VERSION 5.7 ;
  NOWIREEXTENSIONATPIN ON ;
  DIVIDERCHAR "/" ;
  BUSBITCHARS "[]" ;
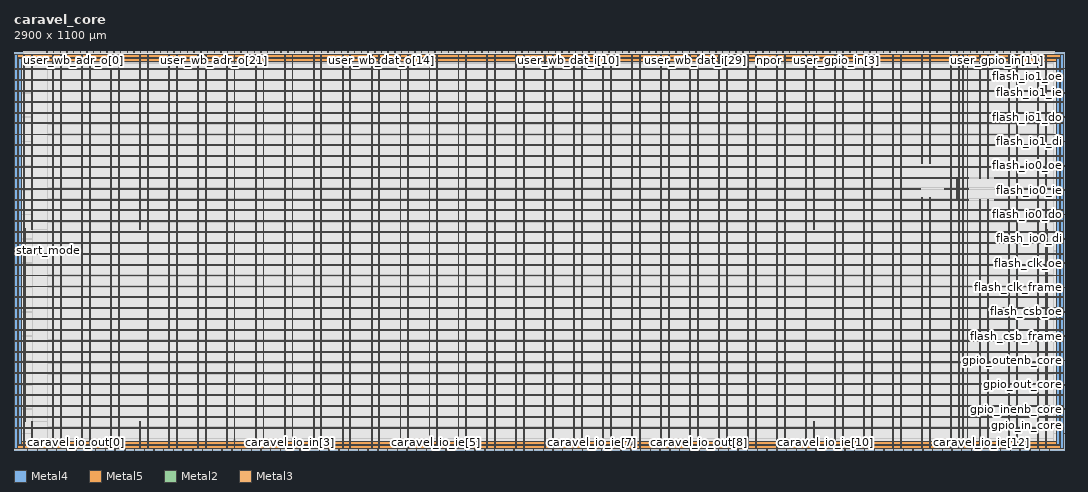
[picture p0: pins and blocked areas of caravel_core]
MACRO caravel_core
  CLASS BLOCK ;
  FOREIGN caravel_core ;
  ORIGIN 0.000 0.000 ;
  SIZE 2900.000 BY 1100.000 ;
  PIN VDD
    DIRECTION INOUT ;
    USE POWER ;
    PORT
      LAYER Metal4 ;
        RECT 11.080 15.360 20.080 1082.240 ;
    END
    PORT
      LAYER Metal5 ;
        RECT 11.080 15.360 2887.480 24.360 ;
    END
    PORT
      LAYER Metal5 ;
        RECT 11.080 1073.240 2887.480 1082.240 ;
    END
    PORT
      LAYER Metal4 ;
        RECT 2878.480 15.360 2887.480 1082.240 ;
    END
    PORT
      LAYER Metal4 ;
        RECT 26.330 4.360 28.830 1093.240 ;
    END
    PORT
      LAYER Metal4 ;
        RECT 106.330 4.360 108.830 1093.240 ;
    END
    PORT
      LAYER Metal4 ;
        RECT 186.330 4.360 188.830 1093.240 ;
    END
    PORT
      LAYER Metal4 ;
        RECT 266.330 4.360 268.830 1093.240 ;
    END
    PORT
      LAYER Metal4 ;
        RECT 346.330 4.360 348.830 78.730 ;
    END
    PORT
      LAYER Metal4 ;
        RECT 346.330 609.370 348.830 1093.240 ;
    END
    PORT
      LAYER Metal4 ;
        RECT 426.330 4.360 428.830 1093.240 ;
    END
    PORT
      LAYER Metal4 ;
        RECT 506.330 4.360 508.830 1093.240 ;
    END
    PORT
      LAYER Metal4 ;
        RECT 586.330 4.360 588.830 1093.240 ;
    END
    PORT
      LAYER Metal4 ;
        RECT 666.330 4.360 668.830 1093.240 ;
    END
    PORT
      LAYER Metal4 ;
        RECT 746.330 4.360 748.830 1093.240 ;
    END
    PORT
      LAYER Metal4 ;
        RECT 826.330 4.360 828.830 1093.240 ;
    END
    PORT
      LAYER Metal4 ;
        RECT 906.330 4.360 908.830 1093.240 ;
    END
    PORT
      LAYER Metal4 ;
        RECT 986.330 4.360 988.830 1093.240 ;
    END
    PORT
      LAYER Metal4 ;
        RECT 1066.330 4.360 1068.830 1093.240 ;
    END
    PORT
      LAYER Metal4 ;
        RECT 1146.330 4.360 1148.830 1093.240 ;
    END
    PORT
      LAYER Metal4 ;
        RECT 1226.330 4.360 1228.830 1093.240 ;
    END
    PORT
      LAYER Metal4 ;
        RECT 1306.330 4.360 1308.830 1093.240 ;
    END
    PORT
      LAYER Metal4 ;
        RECT 1386.330 4.360 1388.830 1093.240 ;
    END
    PORT
      LAYER Metal4 ;
        RECT 1466.330 4.360 1468.830 1093.240 ;
    END
    PORT
      LAYER Metal4 ;
        RECT 1546.330 4.360 1548.830 1093.240 ;
    END
    PORT
      LAYER Metal4 ;
        RECT 1626.330 4.360 1628.830 1093.240 ;
    END
    PORT
      LAYER Metal4 ;
        RECT 1706.330 4.360 1708.830 1093.240 ;
    END
    PORT
      LAYER Metal4 ;
        RECT 1786.330 4.360 1788.830 1093.240 ;
    END
    PORT
      LAYER Metal4 ;
        RECT 1866.330 4.360 1868.830 1093.240 ;
    END
    PORT
      LAYER Metal4 ;
        RECT 1946.330 4.360 1948.830 1093.240 ;
    END
    PORT
      LAYER Metal4 ;
        RECT 2026.330 4.360 2028.830 1093.240 ;
    END
    PORT
      LAYER Metal4 ;
        RECT 2106.330 4.360 2108.830 1093.240 ;
    END
    PORT
      LAYER Metal4 ;
        RECT 2186.330 4.360 2188.830 1093.240 ;
    END
    PORT
      LAYER Metal4 ;
        RECT 2266.330 4.360 2268.830 1093.240 ;
    END
    PORT
      LAYER Metal4 ;
        RECT 2346.330 4.360 2348.830 1093.240 ;
    END
    PORT
      LAYER Metal4 ;
        RECT 2426.330 4.360 2428.830 1093.240 ;
    END
    PORT
      LAYER Metal4 ;
        RECT 2506.330 4.360 2508.830 697.970 ;
    END
    PORT
      LAYER Metal4 ;
        RECT 2506.330 791.630 2508.830 1093.240 ;
    END
    PORT
      LAYER Metal4 ;
        RECT 2586.330 4.360 2588.830 1093.240 ;
    END
    PORT
      LAYER Metal4 ;
        RECT 2666.330 4.360 2668.830 691.730 ;
    END
    PORT
      LAYER Metal4 ;
        RECT 2666.330 749.725 2668.830 1093.240 ;
    END
    PORT
      LAYER Metal4 ;
        RECT 2746.330 4.360 2748.830 1093.240 ;
    END
    PORT
      LAYER Metal4 ;
        RECT 2826.330 4.360 2828.830 1093.240 ;
    END
    PORT
      LAYER Metal5 ;
        RECT 0.080 60.760 2898.480 63.260 ;
    END
    PORT
      LAYER Metal5 ;
        RECT 0.080 120.760 2898.480 123.260 ;
    END
    PORT
      LAYER Metal5 ;
        RECT 0.080 180.760 2898.480 183.260 ;
    END
    PORT
      LAYER Metal5 ;
        RECT 0.080 240.760 2898.480 243.260 ;
    END
    PORT
      LAYER Metal5 ;
        RECT 0.080 300.760 2898.480 303.260 ;
    END
    PORT
      LAYER Metal5 ;
        RECT 0.080 360.760 2898.480 363.260 ;
    END
    PORT
      LAYER Metal5 ;
        RECT 0.080 420.760 2898.480 423.260 ;
    END
    PORT
      LAYER Metal5 ;
        RECT 0.080 480.760 2898.480 483.260 ;
    END
    PORT
      LAYER Metal5 ;
        RECT 0.080 540.760 2898.480 543.260 ;
    END
    PORT
      LAYER Metal5 ;
        RECT 0.080 600.760 2898.480 603.260 ;
    END
    PORT
      LAYER Metal5 ;
        RECT 0.080 660.760 2898.480 663.260 ;
    END
    PORT
      LAYER Metal5 ;
        RECT 0.080 720.760 2504.180 723.260 ;
    END
    PORT
      LAYER Metal5 ;
        RECT 0.080 780.760 2898.480 783.260 ;
    END
    PORT
      LAYER Metal5 ;
        RECT 0.080 840.760 2898.480 843.260 ;
    END
    PORT
      LAYER Metal5 ;
        RECT 0.080 900.760 2898.480 903.260 ;
    END
    PORT
      LAYER Metal5 ;
        RECT 0.080 960.760 2898.480 963.260 ;
    END
    PORT
      LAYER Metal5 ;
        RECT 0.080 1020.760 2898.480 1023.260 ;
    END
    PORT
      LAYER Metal5 ;
        RECT 2570.860 720.760 2635.895 723.260 ;
    END
    PORT
      LAYER Metal5 ;
        RECT 2707.455 720.760 2898.480 723.260 ;
    END
    PORT
      LAYER Metal4 ;
        RECT 2620.830 4.360 2623.330 1093.240 ;
    END
    PORT
      LAYER Metal4 ;
        RECT 2603.095 689.620 2604.345 752.940 ;
    END
    PORT
      LAYER Metal4 ;
        RECT 2851.670 74.180 2854.170 607.900 ;
    END
  END VDD
  PIN VSS
    DIRECTION INOUT ;
    USE GROUND ;
    PORT
      LAYER Metal4 ;
        RECT 0.080 4.360 9.080 1093.240 ;
    END
    PORT
      LAYER Metal5 ;
        RECT 0.080 4.360 2898.480 13.360 ;
    END
    PORT
      LAYER Metal5 ;
        RECT 0.080 1084.240 2898.480 1093.240 ;
    END
    PORT
      LAYER Metal4 ;
        RECT 2889.480 4.360 2898.480 1093.240 ;
    END
    PORT
      LAYER Metal4 ;
        RECT 47.830 4.360 50.330 78.730 ;
    END
    PORT
      LAYER Metal4 ;
        RECT 47.830 609.370 50.330 1093.240 ;
    END
    PORT
      LAYER Metal4 ;
        RECT 127.830 4.360 130.330 1093.240 ;
    END
    PORT
      LAYER Metal4 ;
        RECT 207.830 4.360 210.330 1093.240 ;
    END
    PORT
      LAYER Metal4 ;
        RECT 287.830 4.360 290.330 1093.240 ;
    END
    PORT
      LAYER Metal4 ;
        RECT 367.830 4.360 370.330 1093.240 ;
    END
    PORT
      LAYER Metal4 ;
        RECT 447.830 4.360 450.330 1093.240 ;
    END
    PORT
      LAYER Metal4 ;
        RECT 527.830 4.360 530.330 1093.240 ;
    END
    PORT
      LAYER Metal4 ;
        RECT 607.830 4.360 610.330 1093.240 ;
    END
    PORT
      LAYER Metal4 ;
        RECT 687.830 4.360 690.330 1093.240 ;
    END
    PORT
      LAYER Metal4 ;
        RECT 767.830 4.360 770.330 1093.240 ;
    END
    PORT
      LAYER Metal4 ;
        RECT 847.830 4.360 850.330 1093.240 ;
    END
    PORT
      LAYER Metal4 ;
        RECT 927.830 4.360 930.330 1093.240 ;
    END
    PORT
      LAYER Metal4 ;
        RECT 1007.830 4.360 1010.330 1093.240 ;
    END
    PORT
      LAYER Metal4 ;
        RECT 1087.830 4.360 1090.330 1093.240 ;
    END
    PORT
      LAYER Metal4 ;
        RECT 1167.830 4.360 1170.330 1093.240 ;
    END
    PORT
      LAYER Metal4 ;
        RECT 1247.830 4.360 1250.330 1093.240 ;
    END
    PORT
      LAYER Metal4 ;
        RECT 1327.830 4.360 1330.330 1093.240 ;
    END
    PORT
      LAYER Metal4 ;
        RECT 1407.830 4.360 1410.330 1093.240 ;
    END
    PORT
      LAYER Metal4 ;
        RECT 1487.830 4.360 1490.330 1093.240 ;
    END
    PORT
      LAYER Metal4 ;
        RECT 1567.830 4.360 1570.330 1093.240 ;
    END
    PORT
      LAYER Metal4 ;
        RECT 1647.830 4.360 1650.330 1093.240 ;
    END
    PORT
      LAYER Metal4 ;
        RECT 1727.830 4.360 1730.330 1093.240 ;
    END
    PORT
      LAYER Metal4 ;
        RECT 1807.830 4.360 1810.330 1093.240 ;
    END
    PORT
      LAYER Metal4 ;
        RECT 1887.830 4.360 1890.330 1093.240 ;
    END
    PORT
      LAYER Metal4 ;
        RECT 1967.830 4.360 1970.330 1093.240 ;
    END
    PORT
      LAYER Metal4 ;
        RECT 2047.830 4.360 2050.330 1093.240 ;
    END
    PORT
      LAYER Metal4 ;
        RECT 2127.830 4.360 2130.330 1093.240 ;
    END
    PORT
      LAYER Metal4 ;
        RECT 2207.830 4.360 2210.330 78.730 ;
    END
    PORT
      LAYER Metal4 ;
        RECT 2207.830 609.370 2210.330 1093.240 ;
    END
    PORT
      LAYER Metal4 ;
        RECT 2287.830 4.360 2290.330 1093.240 ;
    END
    PORT
      LAYER Metal4 ;
        RECT 2367.830 4.360 2370.330 1093.240 ;
    END
    PORT
      LAYER Metal4 ;
        RECT 2447.830 4.360 2450.330 1093.240 ;
    END
    PORT
      LAYER Metal4 ;
        RECT 2527.830 4.360 2530.330 697.970 ;
    END
    PORT
      LAYER Metal4 ;
        RECT 2527.830 791.630 2530.330 1093.240 ;
    END
    PORT
      LAYER Metal4 ;
        RECT 2607.830 4.360 2610.330 1093.240 ;
    END
    PORT
      LAYER Metal4 ;
        RECT 2687.830 4.360 2690.330 691.730 ;
    END
    PORT
      LAYER Metal4 ;
        RECT 2687.830 749.725 2690.330 1093.240 ;
    END
    PORT
      LAYER Metal4 ;
        RECT 2767.830 4.360 2770.330 1093.240 ;
    END
    PORT
      LAYER Metal4 ;
        RECT 2847.830 4.360 2850.330 1093.240 ;
    END
    PORT
      LAYER Metal5 ;
        RECT 0.080 90.260 2898.480 92.760 ;
    END
    PORT
      LAYER Metal5 ;
        RECT 0.080 150.260 2898.480 152.760 ;
    END
    PORT
      LAYER Metal5 ;
        RECT 0.080 210.260 2898.480 212.760 ;
    END
    PORT
      LAYER Metal5 ;
        RECT 0.080 270.260 2898.480 272.760 ;
    END
    PORT
      LAYER Metal5 ;
        RECT 0.080 330.260 2898.480 332.760 ;
    END
    PORT
      LAYER Metal5 ;
        RECT 0.080 390.260 2898.480 392.760 ;
    END
    PORT
      LAYER Metal5 ;
        RECT 0.080 450.260 2898.480 452.760 ;
    END
    PORT
      LAYER Metal5 ;
        RECT 0.080 510.260 2898.480 512.760 ;
    END
    PORT
      LAYER Metal5 ;
        RECT 0.080 570.260 2898.480 572.760 ;
    END
    PORT
      LAYER Metal5 ;
        RECT 0.080 630.260 2898.480 632.760 ;
    END
    PORT
      LAYER Metal5 ;
        RECT 0.080 690.260 2636.395 692.760 ;
    END
    PORT
      LAYER Metal5 ;
        RECT 0.080 750.260 2635.895 752.760 ;
    END
    PORT
      LAYER Metal5 ;
        RECT 0.080 810.260 2898.480 812.760 ;
    END
    PORT
      LAYER Metal5 ;
        RECT 0.080 870.260 2898.480 872.760 ;
    END
    PORT
      LAYER Metal5 ;
        RECT 0.080 930.260 2898.480 932.760 ;
    END
    PORT
      LAYER Metal5 ;
        RECT 0.080 990.260 2898.480 992.760 ;
    END
    PORT
      LAYER Metal5 ;
        RECT 0.080 1050.260 2898.480 1052.760 ;
    END
    PORT
      LAYER Metal5 ;
        RECT 2707.455 690.260 2898.480 692.760 ;
    END
    PORT
      LAYER Metal5 ;
        RECT 2707.455 750.260 2898.480 752.760 ;
    END
    PORT
      LAYER Metal4 ;
        RECT 2632.330 4.360 2634.830 1093.240 ;
    END
    PORT
      LAYER Metal4 ;
        RECT 30.390 78.100 32.890 611.820 ;
    END
    PORT
      LAYER Metal4 ;
        RECT 2604.775 689.620 2606.025 752.940 ;
    END
  END VSS
  PIN caravel_io_ie[0]
    DIRECTION OUTPUT ;
    USE SIGNAL ;
    ANTENNADIFFAREA 1.237600 ;
    PORT
      LAYER Metal2 ;
        RECT 90.440 0.000 91.560 1.120 ;
    END
  END caravel_io_ie[0]
  PIN caravel_io_ie[10]
    DIRECTION OUTPUT ;
    USE SIGNAL ;
    ANTENNADIFFAREA 1.237600 ;
    PORT
      LAYER Metal2 ;
        RECT 2240.840 0.000 2241.960 1.120 ;
    END
  END caravel_io_ie[10]
  PIN caravel_io_ie[11]
    DIRECTION OUTPUT ;
    USE SIGNAL ;
    ANTENNADIFFAREA 1.237600 ;
    PORT
      LAYER Metal2 ;
        RECT 2455.880 0.000 2457.000 1.120 ;
    END
  END caravel_io_ie[11]
  PIN caravel_io_ie[12]
    DIRECTION OUTPUT ;
    USE SIGNAL ;
    ANTENNADIFFAREA 1.237600 ;
    PORT
      LAYER Metal2 ;
        RECT 2670.920 0.000 2672.040 1.120 ;
    END
  END caravel_io_ie[12]
  PIN caravel_io_ie[1]
    DIRECTION OUTPUT ;
    USE SIGNAL ;
    ANTENNADIFFAREA 1.237600 ;
    PORT
      LAYER Metal2 ;
        RECT 305.480 0.000 306.600 1.120 ;
    END
  END caravel_io_ie[1]
  PIN caravel_io_ie[2]
    DIRECTION OUTPUT ;
    USE SIGNAL ;
    ANTENNADIFFAREA 1.237600 ;
    PORT
      LAYER Metal2 ;
        RECT 520.520 0.000 521.640 1.120 ;
    END
  END caravel_io_ie[2]
  PIN caravel_io_ie[3]
    DIRECTION OUTPUT ;
    USE SIGNAL ;
    ANTENNADIFFAREA 1.237600 ;
    PORT
      LAYER Metal2 ;
        RECT 735.560 0.000 736.680 1.120 ;
    END
  END caravel_io_ie[3]
  PIN caravel_io_ie[4]
    DIRECTION OUTPUT ;
    USE SIGNAL ;
    ANTENNADIFFAREA 1.237600 ;
    PORT
      LAYER Metal2 ;
        RECT 950.600 0.000 951.720 1.120 ;
    END
  END caravel_io_ie[4]
  PIN caravel_io_ie[5]
    DIRECTION OUTPUT ;
    USE SIGNAL ;
    ANTENNADIFFAREA 1.237600 ;
    PORT
      LAYER Metal2 ;
        RECT 1165.640 0.000 1166.760 1.120 ;
    END
  END caravel_io_ie[5]
  PIN caravel_io_ie[6]
    DIRECTION OUTPUT ;
    USE SIGNAL ;
    ANTENNADIFFAREA 1.237600 ;
    PORT
      LAYER Metal2 ;
        RECT 1380.680 0.000 1381.800 1.120 ;
    END
  END caravel_io_ie[6]
  PIN caravel_io_ie[7]
    DIRECTION OUTPUT ;
    USE SIGNAL ;
    ANTENNADIFFAREA 1.237600 ;
    PORT
      LAYER Metal2 ;
        RECT 1595.720 0.000 1596.840 1.120 ;
    END
  END caravel_io_ie[7]
  PIN caravel_io_ie[8]
    DIRECTION OUTPUT ;
    USE SIGNAL ;
    ANTENNADIFFAREA 1.237600 ;
    PORT
      LAYER Metal2 ;
        RECT 1810.760 0.000 1811.880 1.120 ;
    END
  END caravel_io_ie[8]
  PIN caravel_io_ie[9]
    DIRECTION OUTPUT ;
    USE SIGNAL ;
    ANTENNADIFFAREA 1.237600 ;
    PORT
      LAYER Metal2 ;
        RECT 2025.800 0.000 2026.920 1.120 ;
    END
  END caravel_io_ie[9]
  PIN caravel_io_in[0]
    DIRECTION INPUT ;
    USE SIGNAL ;
    ANTENNAGATEAREA 0.666400 ;
    ANTENNADIFFAREA 0.438500 ;
    PORT
      LAYER Metal2 ;
        RECT 117.320 0.000 118.440 1.120 ;
    END
  END caravel_io_in[0]
  PIN caravel_io_in[10]
    DIRECTION INPUT ;
    USE SIGNAL ;
    ANTENNAGATEAREA 2.430400 ;
    ANTENNADIFFAREA 0.877000 ;
    PORT
      LAYER Metal2 ;
        RECT 2267.720 0.000 2268.840 1.120 ;
    END
  END caravel_io_in[10]
  PIN caravel_io_in[11]
    DIRECTION INPUT ;
    USE SIGNAL ;
    ANTENNAGATEAREA 2.430400 ;
    ANTENNADIFFAREA 0.877000 ;
    PORT
      LAYER Metal2 ;
        RECT 2482.760 0.000 2483.880 1.120 ;
    END
  END caravel_io_in[11]
  PIN caravel_io_in[12]
    DIRECTION INPUT ;
    USE SIGNAL ;
    ANTENNAGATEAREA 2.430400 ;
    ANTENNADIFFAREA 0.877000 ;
    PORT
      LAYER Metal2 ;
        RECT 2697.800 0.000 2698.920 1.120 ;
    END
  END caravel_io_in[12]
  PIN caravel_io_in[1]
    DIRECTION INPUT ;
    USE SIGNAL ;
    ANTENNAGATEAREA 0.666400 ;
    ANTENNADIFFAREA 0.438500 ;
    PORT
      LAYER Metal2 ;
        RECT 332.360 0.000 333.480 1.120 ;
    END
  END caravel_io_in[1]
  PIN caravel_io_in[2]
    DIRECTION INPUT ;
    USE SIGNAL ;
    ANTENNAGATEAREA 0.666400 ;
    ANTENNADIFFAREA 0.438500 ;
    PORT
      LAYER Metal2 ;
        RECT 547.400 0.000 548.520 1.120 ;
    END
  END caravel_io_in[2]
  PIN caravel_io_in[3]
    DIRECTION INPUT ;
    USE SIGNAL ;
    ANTENNAGATEAREA 0.666400 ;
    ANTENNADIFFAREA 0.438500 ;
    PORT
      LAYER Metal2 ;
        RECT 762.440 0.000 763.560 1.120 ;
    END
  END caravel_io_in[3]
  PIN caravel_io_in[4]
    DIRECTION INPUT ;
    USE SIGNAL ;
    ANTENNAGATEAREA 4.704000 ;
    ANTENNADIFFAREA 0.877000 ;
    PORT
      LAYER Metal2 ;
        RECT 977.480 0.000 978.600 1.120 ;
    END
  END caravel_io_in[4]
  PIN caravel_io_in[5]
    DIRECTION INPUT ;
    USE SIGNAL ;
    ANTENNAGATEAREA 0.666400 ;
    ANTENNADIFFAREA 0.438500 ;
    PORT
      LAYER Metal2 ;
        RECT 1192.520 0.000 1193.640 1.120 ;
    END
  END caravel_io_in[5]
  PIN caravel_io_in[6]
    DIRECTION INPUT ;
    USE SIGNAL ;
    ANTENNAGATEAREA 0.666400 ;
    ANTENNADIFFAREA 0.438500 ;
    PORT
      LAYER Metal2 ;
        RECT 1407.560 0.000 1408.680 1.120 ;
    END
  END caravel_io_in[6]
  PIN caravel_io_in[7]
    DIRECTION INPUT ;
    USE SIGNAL ;
    ANTENNAGATEAREA 1.999200 ;
    ANTENNADIFFAREA 0.877000 ;
    PORT
      LAYER Metal2 ;
        RECT 1622.600 0.000 1623.720 1.120 ;
    END
  END caravel_io_in[7]
  PIN caravel_io_in[8]
    DIRECTION INPUT ;
    USE SIGNAL ;
    ANTENNAGATEAREA 1.999200 ;
    ANTENNADIFFAREA 0.438500 ;
    PORT
      LAYER Metal2 ;
        RECT 1837.640 0.000 1838.760 1.120 ;
    END
  END caravel_io_in[8]
  PIN caravel_io_in[9]
    DIRECTION INPUT ;
    USE SIGNAL ;
    ANTENNAGATEAREA 2.352000 ;
    ANTENNADIFFAREA 0.438500 ;
    PORT
      LAYER Metal2 ;
        RECT 2052.680 0.000 2053.800 1.120 ;
    END
  END caravel_io_in[9]
  PIN caravel_io_oe[0]
    DIRECTION OUTPUT ;
    USE SIGNAL ;
    ANTENNADIFFAREA 1.237600 ;
    PORT
      LAYER Metal2 ;
        RECT 144.200 0.000 145.320 1.120 ;
    END
  END caravel_io_oe[0]
  PIN caravel_io_oe[10]
    DIRECTION OUTPUT ;
    USE SIGNAL ;
    ANTENNADIFFAREA 1.237600 ;
    PORT
      LAYER Metal2 ;
        RECT 2294.600 0.000 2295.720 1.120 ;
    END
  END caravel_io_oe[10]
  PIN caravel_io_oe[11]
    DIRECTION OUTPUT ;
    USE SIGNAL ;
    ANTENNADIFFAREA 1.237600 ;
    PORT
      LAYER Metal2 ;
        RECT 2509.640 0.000 2510.760 1.120 ;
    END
  END caravel_io_oe[11]
  PIN caravel_io_oe[12]
    DIRECTION OUTPUT ;
    USE SIGNAL ;
    ANTENNADIFFAREA 1.237600 ;
    PORT
      LAYER Metal2 ;
        RECT 2724.680 0.000 2725.800 1.120 ;
    END
  END caravel_io_oe[12]
  PIN caravel_io_oe[1]
    DIRECTION OUTPUT ;
    USE SIGNAL ;
    ANTENNADIFFAREA 1.237600 ;
    PORT
      LAYER Metal2 ;
        RECT 359.240 0.000 360.360 1.120 ;
    END
  END caravel_io_oe[1]
  PIN caravel_io_oe[2]
    DIRECTION OUTPUT ;
    USE SIGNAL ;
    ANTENNADIFFAREA 1.237600 ;
    PORT
      LAYER Metal2 ;
        RECT 574.280 0.000 575.400 1.120 ;
    END
  END caravel_io_oe[2]
  PIN caravel_io_oe[3]
    DIRECTION OUTPUT ;
    USE SIGNAL ;
    ANTENNADIFFAREA 1.237600 ;
    PORT
      LAYER Metal2 ;
        RECT 789.320 0.000 790.440 1.120 ;
    END
  END caravel_io_oe[3]
  PIN caravel_io_oe[4]
    DIRECTION OUTPUT ;
    USE SIGNAL ;
    ANTENNADIFFAREA 1.237600 ;
    PORT
      LAYER Metal2 ;
        RECT 1004.360 0.000 1005.480 1.120 ;
    END
  END caravel_io_oe[4]
  PIN caravel_io_oe[5]
    DIRECTION OUTPUT ;
    USE SIGNAL ;
    ANTENNADIFFAREA 1.237600 ;
    PORT
      LAYER Metal2 ;
        RECT 1219.400 0.000 1220.520 1.120 ;
    END
  END caravel_io_oe[5]
  PIN caravel_io_oe[6]
    DIRECTION OUTPUT ;
    USE SIGNAL ;
    ANTENNADIFFAREA 1.237600 ;
    PORT
      LAYER Metal2 ;
        RECT 1434.440 0.000 1435.560 1.120 ;
    END
  END caravel_io_oe[6]
  PIN caravel_io_oe[7]
    DIRECTION OUTPUT ;
    USE SIGNAL ;
    ANTENNADIFFAREA 1.237600 ;
    PORT
      LAYER Metal2 ;
        RECT 1649.480 0.000 1650.600 1.120 ;
    END
  END caravel_io_oe[7]
  PIN caravel_io_oe[8]
    DIRECTION OUTPUT ;
    USE SIGNAL ;
    ANTENNADIFFAREA 1.237600 ;
    PORT
      LAYER Metal2 ;
        RECT 1864.520 0.000 1865.640 1.120 ;
    END
  END caravel_io_oe[8]
  PIN caravel_io_oe[9]
    DIRECTION OUTPUT ;
    USE SIGNAL ;
    ANTENNADIFFAREA 1.237600 ;
    PORT
      LAYER Metal2 ;
        RECT 2079.560 0.000 2080.680 1.120 ;
    END
  END caravel_io_oe[9]
  PIN caravel_io_out[0]
    DIRECTION OUTPUT ;
    USE SIGNAL ;
    ANTENNADIFFAREA 1.237600 ;
    PORT
      LAYER Metal2 ;
        RECT 171.080 0.000 172.200 1.120 ;
    END
  END caravel_io_out[0]
  PIN caravel_io_out[10]
    DIRECTION OUTPUT ;
    USE SIGNAL ;
    ANTENNADIFFAREA 1.237600 ;
    PORT
      LAYER Metal2 ;
        RECT 2321.480 0.000 2322.600 1.120 ;
    END
  END caravel_io_out[10]
  PIN caravel_io_out[11]
    DIRECTION OUTPUT ;
    USE SIGNAL ;
    ANTENNADIFFAREA 1.237600 ;
    PORT
      LAYER Metal2 ;
        RECT 2536.520 0.000 2537.640 1.120 ;
    END
  END caravel_io_out[11]
  PIN caravel_io_out[12]
    DIRECTION OUTPUT ;
    USE SIGNAL ;
    ANTENNADIFFAREA 1.237600 ;
    PORT
      LAYER Metal2 ;
        RECT 2751.560 0.000 2752.680 1.120 ;
    END
  END caravel_io_out[12]
  PIN caravel_io_out[1]
    DIRECTION OUTPUT ;
    USE SIGNAL ;
    ANTENNADIFFAREA 1.237600 ;
    PORT
      LAYER Metal2 ;
        RECT 386.120 0.000 387.240 1.120 ;
    END
  END caravel_io_out[1]
  PIN caravel_io_out[2]
    DIRECTION OUTPUT ;
    USE SIGNAL ;
    ANTENNADIFFAREA 1.237600 ;
    PORT
      LAYER Metal2 ;
        RECT 601.160 0.000 602.280 1.120 ;
    END
  END caravel_io_out[2]
  PIN caravel_io_out[3]
    DIRECTION OUTPUT ;
    USE SIGNAL ;
    ANTENNADIFFAREA 1.237600 ;
    PORT
      LAYER Metal2 ;
        RECT 816.200 0.000 817.320 1.120 ;
    END
  END caravel_io_out[3]
  PIN caravel_io_out[4]
    DIRECTION OUTPUT ;
    USE SIGNAL ;
    ANTENNADIFFAREA 1.237600 ;
    PORT
      LAYER Metal2 ;
        RECT 1031.240 0.000 1032.360 1.120 ;
    END
  END caravel_io_out[4]
  PIN caravel_io_out[5]
    DIRECTION OUTPUT ;
    USE SIGNAL ;
    ANTENNADIFFAREA 1.237600 ;
    PORT
      LAYER Metal2 ;
        RECT 1246.280 0.000 1247.400 1.120 ;
    END
  END caravel_io_out[5]
  PIN caravel_io_out[6]
    DIRECTION OUTPUT ;
    USE SIGNAL ;
    ANTENNADIFFAREA 1.237600 ;
    PORT
      LAYER Metal2 ;
        RECT 1461.320 0.000 1462.440 1.120 ;
    END
  END caravel_io_out[6]
  PIN caravel_io_out[7]
    DIRECTION OUTPUT ;
    USE SIGNAL ;
    ANTENNADIFFAREA 1.237600 ;
    PORT
      LAYER Metal2 ;
        RECT 1676.360 0.000 1677.480 1.120 ;
    END
  END caravel_io_out[7]
  PIN caravel_io_out[8]
    DIRECTION OUTPUT ;
    USE SIGNAL ;
    ANTENNADIFFAREA 1.237600 ;
    PORT
      LAYER Metal2 ;
        RECT 1891.400 0.000 1892.520 1.120 ;
    END
  END caravel_io_out[8]
  PIN caravel_io_out[9]
    DIRECTION OUTPUT ;
    USE SIGNAL ;
    ANTENNADIFFAREA 1.237600 ;
    PORT
      LAYER Metal2 ;
        RECT 2106.440 0.000 2107.560 1.120 ;
    END
  END caravel_io_out[9]
  PIN caravel_io_pulldown_sel[0]
    DIRECTION OUTPUT ;
    USE SIGNAL ;
    ANTENNADIFFAREA 1.237600 ;
    PORT
      LAYER Metal2 ;
        RECT 197.960 0.000 199.080 1.120 ;
    END
  END caravel_io_pulldown_sel[0]
  PIN caravel_io_pulldown_sel[10]
    DIRECTION OUTPUT ;
    USE SIGNAL ;
    ANTENNADIFFAREA 1.237600 ;
    PORT
      LAYER Metal2 ;
        RECT 2348.360 0.000 2349.480 1.120 ;
    END
  END caravel_io_pulldown_sel[10]
  PIN caravel_io_pulldown_sel[11]
    DIRECTION OUTPUT ;
    USE SIGNAL ;
    ANTENNADIFFAREA 1.237600 ;
    PORT
      LAYER Metal2 ;
        RECT 2563.400 0.000 2564.520 1.120 ;
    END
  END caravel_io_pulldown_sel[11]
  PIN caravel_io_pulldown_sel[12]
    DIRECTION OUTPUT ;
    USE SIGNAL ;
    ANTENNADIFFAREA 1.237600 ;
    PORT
      LAYER Metal2 ;
        RECT 2778.440 0.000 2779.560 1.120 ;
    END
  END caravel_io_pulldown_sel[12]
  PIN caravel_io_pulldown_sel[1]
    DIRECTION OUTPUT ;
    USE SIGNAL ;
    ANTENNADIFFAREA 1.237600 ;
    PORT
      LAYER Metal2 ;
        RECT 413.000 0.000 414.120 1.120 ;
    END
  END caravel_io_pulldown_sel[1]
  PIN caravel_io_pulldown_sel[2]
    DIRECTION OUTPUT ;
    USE SIGNAL ;
    ANTENNADIFFAREA 1.237600 ;
    PORT
      LAYER Metal2 ;
        RECT 628.040 0.000 629.160 1.120 ;
    END
  END caravel_io_pulldown_sel[2]
  PIN caravel_io_pulldown_sel[3]
    DIRECTION OUTPUT ;
    USE SIGNAL ;
    ANTENNADIFFAREA 1.237600 ;
    PORT
      LAYER Metal2 ;
        RECT 843.080 0.000 844.200 1.120 ;
    END
  END caravel_io_pulldown_sel[3]
  PIN caravel_io_pulldown_sel[4]
    DIRECTION OUTPUT ;
    USE SIGNAL ;
    ANTENNADIFFAREA 1.237600 ;
    PORT
      LAYER Metal2 ;
        RECT 1058.120 0.000 1059.240 1.120 ;
    END
  END caravel_io_pulldown_sel[4]
  PIN caravel_io_pulldown_sel[5]
    DIRECTION OUTPUT ;
    USE SIGNAL ;
    ANTENNADIFFAREA 1.237600 ;
    PORT
      LAYER Metal2 ;
        RECT 1273.160 0.000 1274.280 1.120 ;
    END
  END caravel_io_pulldown_sel[5]
  PIN caravel_io_pulldown_sel[6]
    DIRECTION OUTPUT ;
    USE SIGNAL ;
    ANTENNADIFFAREA 1.237600 ;
    PORT
      LAYER Metal2 ;
        RECT 1488.200 0.000 1489.320 1.120 ;
    END
  END caravel_io_pulldown_sel[6]
  PIN caravel_io_pulldown_sel[7]
    DIRECTION OUTPUT ;
    USE SIGNAL ;
    ANTENNADIFFAREA 1.237600 ;
    PORT
      LAYER Metal2 ;
        RECT 1703.240 0.000 1704.360 1.120 ;
    END
  END caravel_io_pulldown_sel[7]
  PIN caravel_io_pulldown_sel[8]
    DIRECTION OUTPUT ;
    USE SIGNAL ;
    ANTENNADIFFAREA 1.237600 ;
    PORT
      LAYER Metal2 ;
        RECT 1918.280 0.000 1919.400 1.120 ;
    END
  END caravel_io_pulldown_sel[8]
  PIN caravel_io_pulldown_sel[9]
    DIRECTION OUTPUT ;
    USE SIGNAL ;
    ANTENNADIFFAREA 1.237600 ;
    PORT
      LAYER Metal2 ;
        RECT 2133.320 0.000 2134.440 1.120 ;
    END
  END caravel_io_pulldown_sel[9]
  PIN caravel_io_pullup_sel[0]
    DIRECTION OUTPUT ;
    USE SIGNAL ;
    ANTENNADIFFAREA 1.237600 ;
    PORT
      LAYER Metal2 ;
        RECT 224.840 0.000 225.960 1.120 ;
    END
  END caravel_io_pullup_sel[0]
  PIN caravel_io_pullup_sel[10]
    DIRECTION OUTPUT ;
    USE SIGNAL ;
    ANTENNADIFFAREA 1.237600 ;
    PORT
      LAYER Metal2 ;
        RECT 2375.240 0.000 2376.360 1.120 ;
    END
  END caravel_io_pullup_sel[10]
  PIN caravel_io_pullup_sel[11]
    DIRECTION OUTPUT ;
    USE SIGNAL ;
    ANTENNADIFFAREA 1.237600 ;
    PORT
      LAYER Metal2 ;
        RECT 2590.280 0.000 2591.400 1.120 ;
    END
  END caravel_io_pullup_sel[11]
  PIN caravel_io_pullup_sel[12]
    DIRECTION OUTPUT ;
    USE SIGNAL ;
    ANTENNADIFFAREA 1.237600 ;
    PORT
      LAYER Metal2 ;
        RECT 2805.320 0.000 2806.440 1.120 ;
    END
  END caravel_io_pullup_sel[12]
  PIN caravel_io_pullup_sel[1]
    DIRECTION OUTPUT ;
    USE SIGNAL ;
    ANTENNADIFFAREA 1.237600 ;
    PORT
      LAYER Metal2 ;
        RECT 439.880 0.000 441.000 1.120 ;
    END
  END caravel_io_pullup_sel[1]
  PIN caravel_io_pullup_sel[2]
    DIRECTION OUTPUT ;
    USE SIGNAL ;
    ANTENNADIFFAREA 1.237600 ;
    PORT
      LAYER Metal2 ;
        RECT 654.920 0.000 656.040 1.120 ;
    END
  END caravel_io_pullup_sel[2]
  PIN caravel_io_pullup_sel[3]
    DIRECTION OUTPUT ;
    USE SIGNAL ;
    ANTENNADIFFAREA 1.237600 ;
    PORT
      LAYER Metal2 ;
        RECT 869.960 0.000 871.080 1.120 ;
    END
  END caravel_io_pullup_sel[3]
  PIN caravel_io_pullup_sel[4]
    DIRECTION OUTPUT ;
    USE SIGNAL ;
    ANTENNADIFFAREA 1.237600 ;
    PORT
      LAYER Metal2 ;
        RECT 1085.000 0.000 1086.120 1.120 ;
    END
  END caravel_io_pullup_sel[4]
  PIN caravel_io_pullup_sel[5]
    DIRECTION OUTPUT ;
    USE SIGNAL ;
    ANTENNADIFFAREA 1.237600 ;
    PORT
      LAYER Metal2 ;
        RECT 1300.040 0.000 1301.160 1.120 ;
    END
  END caravel_io_pullup_sel[5]
  PIN caravel_io_pullup_sel[6]
    DIRECTION OUTPUT ;
    USE SIGNAL ;
    ANTENNADIFFAREA 1.237600 ;
    PORT
      LAYER Metal2 ;
        RECT 1515.080 0.000 1516.200 1.120 ;
    END
  END caravel_io_pullup_sel[6]
  PIN caravel_io_pullup_sel[7]
    DIRECTION OUTPUT ;
    USE SIGNAL ;
    ANTENNADIFFAREA 1.237600 ;
    PORT
      LAYER Metal2 ;
        RECT 1730.120 0.000 1731.240 1.120 ;
    END
  END caravel_io_pullup_sel[7]
  PIN caravel_io_pullup_sel[8]
    DIRECTION OUTPUT ;
    USE SIGNAL ;
    ANTENNADIFFAREA 1.237600 ;
    PORT
      LAYER Metal2 ;
        RECT 1945.160 0.000 1946.280 1.120 ;
    END
  END caravel_io_pullup_sel[8]
  PIN caravel_io_pullup_sel[9]
    DIRECTION OUTPUT ;
    USE SIGNAL ;
    ANTENNADIFFAREA 1.237600 ;
    PORT
      LAYER Metal2 ;
        RECT 2160.200 0.000 2161.320 1.120 ;
    END
  END caravel_io_pullup_sel[9]
  PIN caravel_io_schmitt_sel[0]
    DIRECTION OUTPUT ;
    USE SIGNAL ;
    ANTENNADIFFAREA 1.237600 ;
    PORT
      LAYER Metal2 ;
        RECT 251.720 0.000 252.840 1.120 ;
    END
  END caravel_io_schmitt_sel[0]
  PIN caravel_io_schmitt_sel[10]
    DIRECTION OUTPUT ;
    USE SIGNAL ;
    ANTENNADIFFAREA 1.237600 ;
    PORT
      LAYER Metal2 ;
        RECT 2402.120 0.000 2403.240 1.120 ;
    END
  END caravel_io_schmitt_sel[10]
  PIN caravel_io_schmitt_sel[11]
    DIRECTION OUTPUT ;
    USE SIGNAL ;
    ANTENNADIFFAREA 1.237600 ;
    PORT
      LAYER Metal2 ;
        RECT 2617.160 0.000 2618.280 1.120 ;
    END
  END caravel_io_schmitt_sel[11]
  PIN caravel_io_schmitt_sel[12]
    DIRECTION OUTPUT ;
    USE SIGNAL ;
    ANTENNADIFFAREA 1.237600 ;
    PORT
      LAYER Metal2 ;
        RECT 2832.200 0.000 2833.320 1.120 ;
    END
  END caravel_io_schmitt_sel[12]
  PIN caravel_io_schmitt_sel[1]
    DIRECTION OUTPUT ;
    USE SIGNAL ;
    ANTENNADIFFAREA 1.237600 ;
    PORT
      LAYER Metal2 ;
        RECT 466.760 0.000 467.880 1.120 ;
    END
  END caravel_io_schmitt_sel[1]
  PIN caravel_io_schmitt_sel[2]
    DIRECTION OUTPUT ;
    USE SIGNAL ;
    ANTENNADIFFAREA 1.237600 ;
    PORT
      LAYER Metal2 ;
        RECT 681.800 0.000 682.920 1.120 ;
    END
  END caravel_io_schmitt_sel[2]
  PIN caravel_io_schmitt_sel[3]
    DIRECTION OUTPUT ;
    USE SIGNAL ;
    ANTENNADIFFAREA 1.237600 ;
    PORT
      LAYER Metal2 ;
        RECT 896.840 0.000 897.960 1.120 ;
    END
  END caravel_io_schmitt_sel[3]
  PIN caravel_io_schmitt_sel[4]
    DIRECTION OUTPUT ;
    USE SIGNAL ;
    ANTENNADIFFAREA 1.237600 ;
    PORT
      LAYER Metal2 ;
        RECT 1111.880 0.000 1113.000 1.120 ;
    END
  END caravel_io_schmitt_sel[4]
  PIN caravel_io_schmitt_sel[5]
    DIRECTION OUTPUT ;
    USE SIGNAL ;
    ANTENNADIFFAREA 1.237600 ;
    PORT
      LAYER Metal2 ;
        RECT 1326.920 0.000 1328.040 1.120 ;
    END
  END caravel_io_schmitt_sel[5]
  PIN caravel_io_schmitt_sel[6]
    DIRECTION OUTPUT ;
    USE SIGNAL ;
    ANTENNADIFFAREA 1.237600 ;
    PORT
      LAYER Metal2 ;
        RECT 1541.960 0.000 1543.080 1.120 ;
    END
  END caravel_io_schmitt_sel[6]
  PIN caravel_io_schmitt_sel[7]
    DIRECTION OUTPUT ;
    USE SIGNAL ;
    ANTENNADIFFAREA 1.237600 ;
    PORT
      LAYER Metal2 ;
        RECT 1757.000 0.000 1758.120 1.120 ;
    END
  END caravel_io_schmitt_sel[7]
  PIN caravel_io_schmitt_sel[8]
    DIRECTION OUTPUT ;
    USE SIGNAL ;
    ANTENNADIFFAREA 1.237600 ;
    PORT
      LAYER Metal2 ;
        RECT 1972.040 0.000 1973.160 1.120 ;
    END
  END caravel_io_schmitt_sel[8]
  PIN caravel_io_schmitt_sel[9]
    DIRECTION OUTPUT ;
    USE SIGNAL ;
    ANTENNADIFFAREA 1.237600 ;
    PORT
      LAYER Metal2 ;
        RECT 2187.080 0.000 2188.200 1.120 ;
    END
  END caravel_io_schmitt_sel[9]
  PIN caravel_io_slew_sel[0]
    DIRECTION OUTPUT ;
    USE SIGNAL ;
    ANTENNADIFFAREA 1.237600 ;
    PORT
      LAYER Metal2 ;
        RECT 278.600 0.000 279.720 1.120 ;
    END
  END caravel_io_slew_sel[0]
  PIN caravel_io_slew_sel[10]
    DIRECTION OUTPUT ;
    USE SIGNAL ;
    ANTENNADIFFAREA 1.237600 ;
    PORT
      LAYER Metal2 ;
        RECT 2429.000 0.000 2430.120 1.120 ;
    END
  END caravel_io_slew_sel[10]
  PIN caravel_io_slew_sel[11]
    DIRECTION OUTPUT ;
    USE SIGNAL ;
    ANTENNADIFFAREA 1.237600 ;
    PORT
      LAYER Metal2 ;
        RECT 2644.040 0.000 2645.160 1.120 ;
    END
  END caravel_io_slew_sel[11]
  PIN caravel_io_slew_sel[12]
    DIRECTION OUTPUT ;
    USE SIGNAL ;
    ANTENNADIFFAREA 1.237600 ;
    PORT
      LAYER Metal2 ;
        RECT 2859.080 0.000 2860.200 1.120 ;
    END
  END caravel_io_slew_sel[12]
  PIN caravel_io_slew_sel[1]
    DIRECTION OUTPUT ;
    USE SIGNAL ;
    ANTENNADIFFAREA 1.237600 ;
    PORT
      LAYER Metal2 ;
        RECT 493.640 0.000 494.760 1.120 ;
    END
  END caravel_io_slew_sel[1]
  PIN caravel_io_slew_sel[2]
    DIRECTION OUTPUT ;
    USE SIGNAL ;
    ANTENNADIFFAREA 1.237600 ;
    PORT
      LAYER Metal2 ;
        RECT 708.680 0.000 709.800 1.120 ;
    END
  END caravel_io_slew_sel[2]
  PIN caravel_io_slew_sel[3]
    DIRECTION OUTPUT ;
    USE SIGNAL ;
    ANTENNADIFFAREA 1.237600 ;
    PORT
      LAYER Metal2 ;
        RECT 923.720 0.000 924.840 1.120 ;
    END
  END caravel_io_slew_sel[3]
  PIN caravel_io_slew_sel[4]
    DIRECTION OUTPUT ;
    USE SIGNAL ;
    ANTENNADIFFAREA 1.237600 ;
    PORT
      LAYER Metal2 ;
        RECT 1138.760 0.000 1139.880 1.120 ;
    END
  END caravel_io_slew_sel[4]
  PIN caravel_io_slew_sel[5]
    DIRECTION OUTPUT ;
    USE SIGNAL ;
    ANTENNADIFFAREA 1.237600 ;
    PORT
      LAYER Metal2 ;
        RECT 1353.800 0.000 1354.920 1.120 ;
    END
  END caravel_io_slew_sel[5]
  PIN caravel_io_slew_sel[6]
    DIRECTION OUTPUT ;
    USE SIGNAL ;
    ANTENNADIFFAREA 1.237600 ;
    PORT
      LAYER Metal2 ;
        RECT 1568.840 0.000 1569.960 1.120 ;
    END
  END caravel_io_slew_sel[6]
  PIN caravel_io_slew_sel[7]
    DIRECTION OUTPUT ;
    USE SIGNAL ;
    ANTENNADIFFAREA 1.237600 ;
    PORT
      LAYER Metal2 ;
        RECT 1783.880 0.000 1785.000 1.120 ;
    END
  END caravel_io_slew_sel[7]
  PIN caravel_io_slew_sel[8]
    DIRECTION OUTPUT ;
    USE SIGNAL ;
    ANTENNADIFFAREA 1.237600 ;
    PORT
      LAYER Metal2 ;
        RECT 1998.920 0.000 2000.040 1.120 ;
    END
  END caravel_io_slew_sel[8]
  PIN caravel_io_slew_sel[9]
    DIRECTION OUTPUT ;
    USE SIGNAL ;
    ANTENNADIFFAREA 1.237600 ;
    PORT
      LAYER Metal2 ;
        RECT 2213.960 0.000 2215.080 1.120 ;
    END
  END caravel_io_slew_sel[9]
  PIN clock_core
    DIRECTION INPUT ;
    USE SIGNAL ;
    ANTENNAGATEAREA 2.352000 ;
    ANTENNADIFFAREA 0.438500 ;
    PORT
      LAYER Metal2 ;
        RECT 36.680 0.000 37.800 1.120 ;
    END
  END clock_core
  PIN flash_clk_frame
    DIRECTION OUTPUT ;
    USE SIGNAL ;
    ANTENNADIFFAREA 6.583500 ;
    PORT
      LAYER Metal3 ;
        RECT 2898.880 448.280 2900.000 449.400 ;
    END
  END flash_clk_frame
  PIN flash_clk_oe
    DIRECTION OUTPUT ;
    USE SIGNAL ;
    ANTENNADIFFAREA 1.237600 ;
    PORT
      LAYER Metal3 ;
        RECT 2898.880 515.480 2900.000 516.600 ;
    END
  END flash_clk_oe
  PIN flash_csb_frame
    DIRECTION OUTPUT ;
    USE SIGNAL ;
    ANTENNADIFFAREA 1.237600 ;
    PORT
      LAYER Metal3 ;
        RECT 2898.880 313.880 2900.000 315.000 ;
    END
  END flash_csb_frame
  PIN flash_csb_oe
    DIRECTION OUTPUT ;
    USE SIGNAL ;
    ANTENNADIFFAREA 1.237600 ;
    PORT
      LAYER Metal3 ;
        RECT 2898.880 381.080 2900.000 382.200 ;
    END
  END flash_csb_oe
  PIN flash_io0_di
    DIRECTION INPUT ;
    USE SIGNAL ;
    PORT
      LAYER Metal3 ;
        RECT 2898.880 582.680 2900.000 583.800 ;
    END
  END flash_io0_di
  PIN flash_io0_do
    DIRECTION OUTPUT ;
    USE SIGNAL ;
    ANTENNADIFFAREA 1.237600 ;
    PORT
      LAYER Metal3 ;
        RECT 2898.880 649.880 2900.000 651.000 ;
    END
  END flash_io0_do
  PIN flash_io0_ie
    DIRECTION OUTPUT ;
    USE SIGNAL ;
    ANTENNADIFFAREA 1.237600 ;
    PORT
      LAYER Metal3 ;
        RECT 2898.880 717.080 2900.000 718.200 ;
    END
  END flash_io0_ie
  PIN flash_io0_oe
    DIRECTION OUTPUT ;
    USE SIGNAL ;
    ANTENNADIFFAREA 1.237600 ;
    PORT
      LAYER Metal3 ;
        RECT 2898.880 784.280 2900.000 785.400 ;
    END
  END flash_io0_oe
  PIN flash_io1_di
    DIRECTION INPUT ;
    USE SIGNAL ;
    ANTENNAGATEAREA 0.666400 ;
    ANTENNADIFFAREA 0.438500 ;
    PORT
      LAYER Metal3 ;
        RECT 2898.880 851.480 2900.000 852.600 ;
    END
  END flash_io1_di
  PIN flash_io1_do
    DIRECTION OUTPUT ;
    USE SIGNAL ;
    ANTENNADIFFAREA 0.440000 ;
    PORT
      LAYER Metal3 ;
        RECT 2898.880 918.680 2900.000 919.800 ;
    END
  END flash_io1_do
  PIN flash_io1_ie
    DIRECTION OUTPUT ;
    USE SIGNAL ;
    ANTENNADIFFAREA 0.607200 ;
    PORT
      LAYER Metal3 ;
        RECT 2898.880 985.880 2900.000 987.000 ;
    END
  END flash_io1_ie
  PIN flash_io1_oe
    DIRECTION OUTPUT ;
    USE SIGNAL ;
    ANTENNADIFFAREA 0.440000 ;
    PORT
      LAYER Metal3 ;
        RECT 2898.880 1053.080 2900.000 1054.200 ;
    END
  END flash_io1_oe
  PIN gpio_in_core
    DIRECTION INPUT ;
    USE SIGNAL ;
    ANTENNAGATEAREA 0.666400 ;
    ANTENNADIFFAREA 0.438500 ;
    PORT
      LAYER Metal3 ;
        RECT 2898.880 45.080 2900.000 46.200 ;
    END
  END gpio_in_core
  PIN gpio_inenb_core
    DIRECTION OUTPUT ;
    USE SIGNAL ;
    ANTENNADIFFAREA 1.237600 ;
    PORT
      LAYER Metal3 ;
        RECT 2898.880 112.280 2900.000 113.400 ;
    END
  END gpio_inenb_core
  PIN gpio_out_core
    DIRECTION OUTPUT ;
    USE SIGNAL ;
    ANTENNADIFFAREA 1.237600 ;
    PORT
      LAYER Metal3 ;
        RECT 2898.880 179.480 2900.000 180.600 ;
    END
  END gpio_out_core
  PIN gpio_outenb_core
    DIRECTION OUTPUT ;
    USE SIGNAL ;
    ANTENNADIFFAREA 1.237600 ;
    PORT
      LAYER Metal3 ;
        RECT 2898.880 246.680 2900.000 247.800 ;
    END
  END gpio_outenb_core
  PIN npor
    DIRECTION OUTPUT ;
    USE SIGNAL ;
    ANTENNADIFFAREA 1.237600 ;
    PORT
      LAYER Metal2 ;
        RECT 2086.280 1098.880 2087.400 1100.000 ;
    END
  END npor
  PIN rstb
    DIRECTION INPUT ;
    USE SIGNAL ;
    ANTENNAGATEAREA 0.666400 ;
    ANTENNADIFFAREA 0.438500 ;
    PORT
      LAYER Metal2 ;
        RECT 63.560 0.000 64.680 1.120 ;
    END
  END rstb
  PIN start_mode
    DIRECTION INPUT ;
    USE SIGNAL ;
    ANTENNAGATEAREA 0.666400 ;
    ANTENNADIFFAREA 0.438500 ;
    PORT
      LAYER Metal3 ;
        RECT 0.000 549.080 1.120 550.200 ;
    END
  END start_mode
  PIN user_clock2
    DIRECTION OUTPUT ;
    USE SIGNAL ;
    ANTENNADIFFAREA 1.237600 ;
    PORT
      LAYER Metal2 ;
        RECT 2067.800 1098.880 2068.920 1100.000 ;
    END
  END user_clock2
  PIN user_gpio_in[0]
    DIRECTION OUTPUT ;
    USE SIGNAL ;
    ANTENNADIFFAREA 1.237600 ;
    PORT
      LAYER Metal2 ;
        RECT 2104.760 1098.880 2105.880 1100.000 ;
    END
  END user_gpio_in[0]
  PIN user_gpio_in[10]
    DIRECTION OUTPUT ;
    USE SIGNAL ;
    ANTENNADIFFAREA 1.237600 ;
    PORT
      LAYER Metal2 ;
        RECT 2659.160 1098.880 2660.280 1100.000 ;
    END
  END user_gpio_in[10]
  PIN user_gpio_in[11]
    DIRECTION OUTPUT ;
    USE SIGNAL ;
    ANTENNADIFFAREA 1.237600 ;
    PORT
      LAYER Metal2 ;
        RECT 2714.600 1098.880 2715.720 1100.000 ;
    END
  END user_gpio_in[11]
  PIN user_gpio_in[12]
    DIRECTION OUTPUT ;
    USE SIGNAL ;
    ANTENNADIFFAREA 1.237600 ;
    PORT
      LAYER Metal2 ;
        RECT 2770.040 1098.880 2771.160 1100.000 ;
    END
  END user_gpio_in[12]
  PIN user_gpio_in[1]
    DIRECTION OUTPUT ;
    USE SIGNAL ;
    ANTENNADIFFAREA 1.237600 ;
    PORT
      LAYER Metal2 ;
        RECT 2160.200 1098.880 2161.320 1100.000 ;
    END
  END user_gpio_in[1]
  PIN user_gpio_in[2]
    DIRECTION OUTPUT ;
    USE SIGNAL ;
    ANTENNADIFFAREA 1.237600 ;
    PORT
      LAYER Metal2 ;
        RECT 2215.640 1098.880 2216.760 1100.000 ;
    END
  END user_gpio_in[2]
  PIN user_gpio_in[3]
    DIRECTION OUTPUT ;
    USE SIGNAL ;
    ANTENNADIFFAREA 1.237600 ;
    PORT
      LAYER Metal2 ;
        RECT 2271.080 1098.880 2272.200 1100.000 ;
    END
  END user_gpio_in[3]
  PIN user_gpio_in[4]
    DIRECTION OUTPUT ;
    USE SIGNAL ;
    ANTENNADIFFAREA 1.237600 ;
    PORT
      LAYER Metal2 ;
        RECT 2326.520 1098.880 2327.640 1100.000 ;
    END
  END user_gpio_in[4]
  PIN user_gpio_in[5]
    DIRECTION OUTPUT ;
    USE SIGNAL ;
    ANTENNADIFFAREA 1.237600 ;
    PORT
      LAYER Metal2 ;
        RECT 2381.960 1098.880 2383.080 1100.000 ;
    END
  END user_gpio_in[5]
  PIN user_gpio_in[6]
    DIRECTION OUTPUT ;
    USE SIGNAL ;
    ANTENNADIFFAREA 1.237600 ;
    PORT
      LAYER Metal2 ;
        RECT 2437.400 1098.880 2438.520 1100.000 ;
    END
  END user_gpio_in[6]
  PIN user_gpio_in[7]
    DIRECTION OUTPUT ;
    USE SIGNAL ;
    ANTENNADIFFAREA 1.237600 ;
    PORT
      LAYER Metal2 ;
        RECT 2492.840 1098.880 2493.960 1100.000 ;
    END
  END user_gpio_in[7]
  PIN user_gpio_in[8]
    DIRECTION OUTPUT ;
    USE SIGNAL ;
    ANTENNADIFFAREA 1.237600 ;
    PORT
      LAYER Metal2 ;
        RECT 2548.280 1098.880 2549.400 1100.000 ;
    END
  END user_gpio_in[8]
  PIN user_gpio_in[9]
    DIRECTION OUTPUT ;
    USE SIGNAL ;
    ANTENNADIFFAREA 1.237600 ;
    PORT
      LAYER Metal2 ;
        RECT 2603.720 1098.880 2604.840 1100.000 ;
    END
  END user_gpio_in[9]
  PIN user_gpio_oeb[0]
    DIRECTION INPUT ;
    USE SIGNAL ;
    ANTENNAGATEAREA 0.666400 ;
    ANTENNADIFFAREA 0.438500 ;
    PORT
      LAYER Metal2 ;
        RECT 2123.240 1098.880 2124.360 1100.000 ;
    END
  END user_gpio_oeb[0]
  PIN user_gpio_oeb[10]
    DIRECTION INPUT ;
    USE SIGNAL ;
    ANTENNAGATEAREA 0.666400 ;
    ANTENNADIFFAREA 0.438500 ;
    PORT
      LAYER Metal2 ;
        RECT 2677.640 1098.880 2678.760 1100.000 ;
    END
  END user_gpio_oeb[10]
  PIN user_gpio_oeb[11]
    DIRECTION INPUT ;
    USE SIGNAL ;
    ANTENNAGATEAREA 0.666400 ;
    ANTENNADIFFAREA 0.438500 ;
    PORT
      LAYER Metal2 ;
        RECT 2733.080 1098.880 2734.200 1100.000 ;
    END
  END user_gpio_oeb[11]
  PIN user_gpio_oeb[12]
    DIRECTION INPUT ;
    USE SIGNAL ;
    ANTENNAGATEAREA 0.666400 ;
    ANTENNADIFFAREA 0.438500 ;
    PORT
      LAYER Metal2 ;
        RECT 2788.520 1098.880 2789.640 1100.000 ;
    END
  END user_gpio_oeb[12]
  PIN user_gpio_oeb[1]
    DIRECTION INPUT ;
    USE SIGNAL ;
    ANTENNAGATEAREA 0.666400 ;
    ANTENNADIFFAREA 0.438500 ;
    PORT
      LAYER Metal2 ;
        RECT 2178.680 1098.880 2179.800 1100.000 ;
    END
  END user_gpio_oeb[1]
  PIN user_gpio_oeb[2]
    DIRECTION INPUT ;
    USE SIGNAL ;
    ANTENNAGATEAREA 0.666400 ;
    ANTENNADIFFAREA 0.438500 ;
    PORT
      LAYER Metal2 ;
        RECT 2234.120 1098.880 2235.240 1100.000 ;
    END
  END user_gpio_oeb[2]
  PIN user_gpio_oeb[3]
    DIRECTION INPUT ;
    USE SIGNAL ;
    ANTENNAGATEAREA 0.666400 ;
    ANTENNADIFFAREA 0.438500 ;
    PORT
      LAYER Metal2 ;
        RECT 2289.560 1098.880 2290.680 1100.000 ;
    END
  END user_gpio_oeb[3]
  PIN user_gpio_oeb[4]
    DIRECTION INPUT ;
    USE SIGNAL ;
    ANTENNAGATEAREA 0.666400 ;
    ANTENNADIFFAREA 0.438500 ;
    PORT
      LAYER Metal2 ;
        RECT 2345.000 1098.880 2346.120 1100.000 ;
    END
  END user_gpio_oeb[4]
  PIN user_gpio_oeb[5]
    DIRECTION INPUT ;
    USE SIGNAL ;
    ANTENNAGATEAREA 0.666400 ;
    ANTENNADIFFAREA 0.438500 ;
    PORT
      LAYER Metal2 ;
        RECT 2400.440 1098.880 2401.560 1100.000 ;
    END
  END user_gpio_oeb[5]
  PIN user_gpio_oeb[6]
    DIRECTION INPUT ;
    USE SIGNAL ;
    ANTENNAGATEAREA 0.666400 ;
    ANTENNADIFFAREA 0.438500 ;
    PORT
      LAYER Metal2 ;
        RECT 2455.880 1098.880 2457.000 1100.000 ;
    END
  END user_gpio_oeb[6]
  PIN user_gpio_oeb[7]
    DIRECTION INPUT ;
    USE SIGNAL ;
    ANTENNAGATEAREA 0.666400 ;
    ANTENNADIFFAREA 0.438500 ;
    PORT
      LAYER Metal2 ;
        RECT 2511.320 1098.880 2512.440 1100.000 ;
    END
  END user_gpio_oeb[7]
  PIN user_gpio_oeb[8]
    DIRECTION INPUT ;
    USE SIGNAL ;
    ANTENNAGATEAREA 0.666400 ;
    ANTENNADIFFAREA 0.438500 ;
    PORT
      LAYER Metal2 ;
        RECT 2566.760 1098.880 2567.880 1100.000 ;
    END
  END user_gpio_oeb[8]
  PIN user_gpio_oeb[9]
    DIRECTION INPUT ;
    USE SIGNAL ;
    ANTENNAGATEAREA 0.666400 ;
    ANTENNADIFFAREA 0.438500 ;
    PORT
      LAYER Metal2 ;
        RECT 2622.200 1098.880 2623.320 1100.000 ;
    END
  END user_gpio_oeb[9]
  PIN user_gpio_out[0]
    DIRECTION INPUT ;
    USE SIGNAL ;
    ANTENNAGATEAREA 0.666400 ;
    ANTENNADIFFAREA 0.438500 ;
    PORT
      LAYER Metal2 ;
        RECT 2141.720 1098.880 2142.840 1100.000 ;
    END
  END user_gpio_out[0]
  PIN user_gpio_out[10]
    DIRECTION INPUT ;
    USE SIGNAL ;
    ANTENNAGATEAREA 0.666400 ;
    ANTENNADIFFAREA 0.438500 ;
    PORT
      LAYER Metal2 ;
        RECT 2696.120 1098.880 2697.240 1100.000 ;
    END
  END user_gpio_out[10]
  PIN user_gpio_out[11]
    DIRECTION INPUT ;
    USE SIGNAL ;
    ANTENNAGATEAREA 0.666400 ;
    ANTENNADIFFAREA 0.438500 ;
    PORT
      LAYER Metal2 ;
        RECT 2751.560 1098.880 2752.680 1100.000 ;
    END
  END user_gpio_out[11]
  PIN user_gpio_out[12]
    DIRECTION INPUT ;
    USE SIGNAL ;
    ANTENNAGATEAREA 0.666400 ;
    ANTENNADIFFAREA 0.438500 ;
    PORT
      LAYER Metal2 ;
        RECT 2807.000 1098.880 2808.120 1100.000 ;
    END
  END user_gpio_out[12]
  PIN user_gpio_out[1]
    DIRECTION INPUT ;
    USE SIGNAL ;
    ANTENNAGATEAREA 0.666400 ;
    ANTENNADIFFAREA 0.438500 ;
    PORT
      LAYER Metal2 ;
        RECT 2197.160 1098.880 2198.280 1100.000 ;
    END
  END user_gpio_out[1]
  PIN user_gpio_out[2]
    DIRECTION INPUT ;
    USE SIGNAL ;
    ANTENNAGATEAREA 0.666400 ;
    ANTENNADIFFAREA 0.438500 ;
    PORT
      LAYER Metal2 ;
        RECT 2252.600 1098.880 2253.720 1100.000 ;
    END
  END user_gpio_out[2]
  PIN user_gpio_out[3]
    DIRECTION INPUT ;
    USE SIGNAL ;
    ANTENNAGATEAREA 0.666400 ;
    ANTENNADIFFAREA 0.438500 ;
    PORT
      LAYER Metal2 ;
        RECT 2308.040 1098.880 2309.160 1100.000 ;
    END
  END user_gpio_out[3]
  PIN user_gpio_out[4]
    DIRECTION INPUT ;
    USE SIGNAL ;
    ANTENNAGATEAREA 0.666400 ;
    ANTENNADIFFAREA 0.438500 ;
    PORT
      LAYER Metal2 ;
        RECT 2363.480 1098.880 2364.600 1100.000 ;
    END
  END user_gpio_out[4]
  PIN user_gpio_out[5]
    DIRECTION INPUT ;
    USE SIGNAL ;
    ANTENNAGATEAREA 0.666400 ;
    ANTENNADIFFAREA 0.438500 ;
    PORT
      LAYER Metal2 ;
        RECT 2418.920 1098.880 2420.040 1100.000 ;
    END
  END user_gpio_out[5]
  PIN user_gpio_out[6]
    DIRECTION INPUT ;
    USE SIGNAL ;
    ANTENNAGATEAREA 0.666400 ;
    ANTENNADIFFAREA 0.438500 ;
    PORT
      LAYER Metal2 ;
        RECT 2474.360 1098.880 2475.480 1100.000 ;
    END
  END user_gpio_out[6]
  PIN user_gpio_out[7]
    DIRECTION INPUT ;
    USE SIGNAL ;
    ANTENNAGATEAREA 0.666400 ;
    ANTENNADIFFAREA 0.438500 ;
    PORT
      LAYER Metal2 ;
        RECT 2529.800 1098.880 2530.920 1100.000 ;
    END
  END user_gpio_out[7]
  PIN user_gpio_out[8]
    DIRECTION INPUT ;
    USE SIGNAL ;
    ANTENNAGATEAREA 0.666400 ;
    ANTENNADIFFAREA 0.438500 ;
    PORT
      LAYER Metal2 ;
        RECT 2585.240 1098.880 2586.360 1100.000 ;
    END
  END user_gpio_out[8]
  PIN user_gpio_out[9]
    DIRECTION INPUT ;
    USE SIGNAL ;
    ANTENNAGATEAREA 0.666400 ;
    ANTENNADIFFAREA 0.438500 ;
    PORT
      LAYER Metal2 ;
        RECT 2640.680 1098.880 2641.800 1100.000 ;
    END
  END user_gpio_out[9]
  PIN user_irq_core
    DIRECTION INPUT ;
    USE SIGNAL ;
    ANTENNAGATEAREA 0.666400 ;
    ANTENNADIFFAREA 0.438500 ;
    PORT
      LAYER Metal2 ;
        RECT 2049.320 1098.880 2050.440 1100.000 ;
    END
  END user_irq_core
  PIN user_wb_ack_i
    DIRECTION INPUT ;
    USE SIGNAL ;
    ANTENNAGATEAREA 0.666400 ;
    ANTENNADIFFAREA 0.438500 ;
    PORT
      LAYER Metal2 ;
        RECT 2012.360 1098.880 2013.480 1100.000 ;
    END
  END user_wb_ack_i
  PIN user_wb_adr_o[0]
    DIRECTION OUTPUT ;
    USE SIGNAL ;
    ANTENNADIFFAREA 0.440000 ;
    PORT
      LAYER Metal2 ;
        RECT 164.360 1098.880 165.480 1100.000 ;
    END
  END user_wb_adr_o[0]
  PIN user_wb_adr_o[10]
    DIRECTION OUTPUT ;
    USE SIGNAL ;
    ANTENNADIFFAREA 1.237600 ;
    PORT
      LAYER Metal2 ;
        RECT 349.160 1098.880 350.280 1100.000 ;
    END
  END user_wb_adr_o[10]
  PIN user_wb_adr_o[11]
    DIRECTION OUTPUT ;
    USE SIGNAL ;
    ANTENNADIFFAREA 1.237600 ;
    PORT
      LAYER Metal2 ;
        RECT 367.640 1098.880 368.760 1100.000 ;
    END
  END user_wb_adr_o[11]
  PIN user_wb_adr_o[12]
    DIRECTION OUTPUT ;
    USE SIGNAL ;
    ANTENNADIFFAREA 1.237600 ;
    PORT
      LAYER Metal2 ;
        RECT 386.120 1098.880 387.240 1100.000 ;
    END
  END user_wb_adr_o[12]
  PIN user_wb_adr_o[13]
    DIRECTION OUTPUT ;
    USE SIGNAL ;
    ANTENNADIFFAREA 1.237600 ;
    PORT
      LAYER Metal2 ;
        RECT 404.600 1098.880 405.720 1100.000 ;
    END
  END user_wb_adr_o[13]
  PIN user_wb_adr_o[14]
    DIRECTION OUTPUT ;
    USE SIGNAL ;
    ANTENNADIFFAREA 1.237600 ;
    PORT
      LAYER Metal2 ;
        RECT 423.080 1098.880 424.200 1100.000 ;
    END
  END user_wb_adr_o[14]
  PIN user_wb_adr_o[15]
    DIRECTION OUTPUT ;
    USE SIGNAL ;
    ANTENNADIFFAREA 1.237600 ;
    PORT
      LAYER Metal2 ;
        RECT 441.560 1098.880 442.680 1100.000 ;
    END
  END user_wb_adr_o[15]
  PIN user_wb_adr_o[16]
    DIRECTION OUTPUT ;
    USE SIGNAL ;
    ANTENNADIFFAREA 1.237600 ;
    PORT
      LAYER Metal2 ;
        RECT 460.040 1098.880 461.160 1100.000 ;
    END
  END user_wb_adr_o[16]
  PIN user_wb_adr_o[17]
    DIRECTION OUTPUT ;
    USE SIGNAL ;
    ANTENNADIFFAREA 1.237600 ;
    PORT
      LAYER Metal2 ;
        RECT 478.520 1098.880 479.640 1100.000 ;
    END
  END user_wb_adr_o[17]
  PIN user_wb_adr_o[18]
    DIRECTION OUTPUT ;
    USE SIGNAL ;
    ANTENNADIFFAREA 1.237600 ;
    PORT
      LAYER Metal2 ;
        RECT 497.000 1098.880 498.120 1100.000 ;
    END
  END user_wb_adr_o[18]
  PIN user_wb_adr_o[19]
    DIRECTION OUTPUT ;
    USE SIGNAL ;
    ANTENNADIFFAREA 1.237600 ;
    PORT
      LAYER Metal2 ;
        RECT 515.480 1098.880 516.600 1100.000 ;
    END
  END user_wb_adr_o[19]
  PIN user_wb_adr_o[1]
    DIRECTION OUTPUT ;
    USE SIGNAL ;
    ANTENNADIFFAREA 0.440000 ;
    PORT
      LAYER Metal2 ;
        RECT 182.840 1098.880 183.960 1100.000 ;
    END
  END user_wb_adr_o[1]
  PIN user_wb_adr_o[20]
    DIRECTION OUTPUT ;
    USE SIGNAL ;
    ANTENNADIFFAREA 1.237600 ;
    PORT
      LAYER Metal2 ;
        RECT 533.960 1098.880 535.080 1100.000 ;
    END
  END user_wb_adr_o[20]
  PIN user_wb_adr_o[21]
    DIRECTION OUTPUT ;
    USE SIGNAL ;
    ANTENNADIFFAREA 1.237600 ;
    PORT
      LAYER Metal2 ;
        RECT 552.440 1098.880 553.560 1100.000 ;
    END
  END user_wb_adr_o[21]
  PIN user_wb_adr_o[22]
    DIRECTION OUTPUT ;
    USE SIGNAL ;
    ANTENNADIFFAREA 1.237600 ;
    PORT
      LAYER Metal2 ;
        RECT 570.920 1098.880 572.040 1100.000 ;
    END
  END user_wb_adr_o[22]
  PIN user_wb_adr_o[23]
    DIRECTION OUTPUT ;
    USE SIGNAL ;
    ANTENNADIFFAREA 1.237600 ;
    PORT
      LAYER Metal2 ;
        RECT 589.400 1098.880 590.520 1100.000 ;
    END
  END user_wb_adr_o[23]
  PIN user_wb_adr_o[24]
    DIRECTION OUTPUT ;
    USE SIGNAL ;
    ANTENNADIFFAREA 1.237600 ;
    PORT
      LAYER Metal2 ;
        RECT 607.880 1098.880 609.000 1100.000 ;
    END
  END user_wb_adr_o[24]
  PIN user_wb_adr_o[25]
    DIRECTION OUTPUT ;
    USE SIGNAL ;
    ANTENNADIFFAREA 1.237600 ;
    PORT
      LAYER Metal2 ;
        RECT 626.360 1098.880 627.480 1100.000 ;
    END
  END user_wb_adr_o[25]
  PIN user_wb_adr_o[26]
    DIRECTION OUTPUT ;
    USE SIGNAL ;
    ANTENNADIFFAREA 1.237600 ;
    PORT
      LAYER Metal2 ;
        RECT 644.840 1098.880 645.960 1100.000 ;
    END
  END user_wb_adr_o[26]
  PIN user_wb_adr_o[27]
    DIRECTION OUTPUT ;
    USE SIGNAL ;
    ANTENNADIFFAREA 1.237600 ;
    PORT
      LAYER Metal2 ;
        RECT 663.320 1098.880 664.440 1100.000 ;
    END
  END user_wb_adr_o[27]
  PIN user_wb_adr_o[28]
    DIRECTION OUTPUT ;
    USE SIGNAL ;
    ANTENNADIFFAREA 1.237600 ;
    PORT
      LAYER Metal2 ;
        RECT 681.800 1098.880 682.920 1100.000 ;
    END
  END user_wb_adr_o[28]
  PIN user_wb_adr_o[29]
    DIRECTION OUTPUT ;
    USE SIGNAL ;
    ANTENNADIFFAREA 1.237600 ;
    PORT
      LAYER Metal2 ;
        RECT 700.280 1098.880 701.400 1100.000 ;
    END
  END user_wb_adr_o[29]
  PIN user_wb_adr_o[2]
    DIRECTION OUTPUT ;
    USE SIGNAL ;
    ANTENNADIFFAREA 1.237600 ;
    PORT
      LAYER Metal2 ;
        RECT 201.320 1098.880 202.440 1100.000 ;
    END
  END user_wb_adr_o[2]
  PIN user_wb_adr_o[30]
    DIRECTION OUTPUT ;
    USE SIGNAL ;
    ANTENNADIFFAREA 1.237600 ;
    PORT
      LAYER Metal2 ;
        RECT 718.760 1098.880 719.880 1100.000 ;
    END
  END user_wb_adr_o[30]
  PIN user_wb_adr_o[31]
    DIRECTION OUTPUT ;
    USE SIGNAL ;
    ANTENNADIFFAREA 1.237600 ;
    PORT
      LAYER Metal2 ;
        RECT 737.240 1098.880 738.360 1100.000 ;
    END
  END user_wb_adr_o[31]
  PIN user_wb_adr_o[3]
    DIRECTION OUTPUT ;
    USE SIGNAL ;
    ANTENNADIFFAREA 1.237600 ;
    PORT
      LAYER Metal2 ;
        RECT 219.800 1098.880 220.920 1100.000 ;
    END
  END user_wb_adr_o[3]
  PIN user_wb_adr_o[4]
    DIRECTION OUTPUT ;
    USE SIGNAL ;
    ANTENNADIFFAREA 1.237600 ;
    PORT
      LAYER Metal2 ;
        RECT 238.280 1098.880 239.400 1100.000 ;
    END
  END user_wb_adr_o[4]
  PIN user_wb_adr_o[5]
    DIRECTION OUTPUT ;
    USE SIGNAL ;
    ANTENNADIFFAREA 1.237600 ;
    PORT
      LAYER Metal2 ;
        RECT 256.760 1098.880 257.880 1100.000 ;
    END
  END user_wb_adr_o[5]
  PIN user_wb_adr_o[6]
    DIRECTION OUTPUT ;
    USE SIGNAL ;
    ANTENNADIFFAREA 1.237600 ;
    PORT
      LAYER Metal2 ;
        RECT 275.240 1098.880 276.360 1100.000 ;
    END
  END user_wb_adr_o[6]
  PIN user_wb_adr_o[7]
    DIRECTION OUTPUT ;
    USE SIGNAL ;
    ANTENNADIFFAREA 1.237600 ;
    PORT
      LAYER Metal2 ;
        RECT 293.720 1098.880 294.840 1100.000 ;
    END
  END user_wb_adr_o[7]
  PIN user_wb_adr_o[8]
    DIRECTION OUTPUT ;
    USE SIGNAL ;
    ANTENNADIFFAREA 1.237600 ;
    PORT
      LAYER Metal2 ;
        RECT 312.200 1098.880 313.320 1100.000 ;
    END
  END user_wb_adr_o[8]
  PIN user_wb_adr_o[9]
    DIRECTION OUTPUT ;
    USE SIGNAL ;
    ANTENNADIFFAREA 1.237600 ;
    PORT
      LAYER Metal2 ;
        RECT 330.680 1098.880 331.800 1100.000 ;
    END
  END user_wb_adr_o[9]
  PIN user_wb_clk_o
    DIRECTION OUTPUT ;
    USE SIGNAL ;
    ANTENNADIFFAREA 6.583500 ;
    PORT
      LAYER Metal2 ;
        RECT 2030.840 1098.880 2031.960 1100.000 ;
    END
  END user_wb_clk_o
  PIN user_wb_cyc_o
    DIRECTION OUTPUT ;
    USE SIGNAL ;
    ANTENNADIFFAREA 1.237600 ;
    PORT
      LAYER Metal2 ;
        RECT 1956.920 1098.880 1958.040 1100.000 ;
    END
  END user_wb_cyc_o
  PIN user_wb_dat_i[0]
    DIRECTION INPUT ;
    USE SIGNAL ;
    ANTENNAGATEAREA 0.666400 ;
    ANTENNADIFFAREA 0.438500 ;
    PORT
      LAYER Metal2 ;
        RECT 1347.080 1098.880 1348.200 1100.000 ;
    END
  END user_wb_dat_i[0]
  PIN user_wb_dat_i[10]
    DIRECTION INPUT ;
    USE SIGNAL ;
    ANTENNAGATEAREA 0.666400 ;
    ANTENNADIFFAREA 0.438500 ;
    PORT
      LAYER Metal2 ;
        RECT 1531.880 1098.880 1533.000 1100.000 ;
    END
  END user_wb_dat_i[10]
  PIN user_wb_dat_i[11]
    DIRECTION INPUT ;
    USE SIGNAL ;
    ANTENNAGATEAREA 0.666400 ;
    ANTENNADIFFAREA 0.438500 ;
    PORT
      LAYER Metal2 ;
        RECT 1550.360 1098.880 1551.480 1100.000 ;
    END
  END user_wb_dat_i[11]
  PIN user_wb_dat_i[12]
    DIRECTION INPUT ;
    USE SIGNAL ;
    ANTENNAGATEAREA 0.666400 ;
    ANTENNADIFFAREA 0.438500 ;
    PORT
      LAYER Metal2 ;
        RECT 1568.840 1098.880 1569.960 1100.000 ;
    END
  END user_wb_dat_i[12]
  PIN user_wb_dat_i[13]
    DIRECTION INPUT ;
    USE SIGNAL ;
    ANTENNAGATEAREA 0.666400 ;
    ANTENNADIFFAREA 0.438500 ;
    PORT
      LAYER Metal2 ;
        RECT 1587.320 1098.880 1588.440 1100.000 ;
    END
  END user_wb_dat_i[13]
  PIN user_wb_dat_i[14]
    DIRECTION INPUT ;
    USE SIGNAL ;
    ANTENNAGATEAREA 0.666400 ;
    ANTENNADIFFAREA 0.438500 ;
    PORT
      LAYER Metal2 ;
        RECT 1605.800 1098.880 1606.920 1100.000 ;
    END
  END user_wb_dat_i[14]
  PIN user_wb_dat_i[15]
    DIRECTION INPUT ;
    USE SIGNAL ;
    ANTENNAGATEAREA 0.666400 ;
    ANTENNADIFFAREA 0.438500 ;
    PORT
      LAYER Metal2 ;
        RECT 1624.280 1098.880 1625.400 1100.000 ;
    END
  END user_wb_dat_i[15]
  PIN user_wb_dat_i[16]
    DIRECTION INPUT ;
    USE SIGNAL ;
    ANTENNAGATEAREA 0.666400 ;
    ANTENNADIFFAREA 0.438500 ;
    PORT
      LAYER Metal2 ;
        RECT 1642.760 1098.880 1643.880 1100.000 ;
    END
  END user_wb_dat_i[16]
  PIN user_wb_dat_i[17]
    DIRECTION INPUT ;
    USE SIGNAL ;
    ANTENNAGATEAREA 0.666400 ;
    ANTENNADIFFAREA 0.438500 ;
    PORT
      LAYER Metal2 ;
        RECT 1661.240 1098.880 1662.360 1100.000 ;
    END
  END user_wb_dat_i[17]
  PIN user_wb_dat_i[18]
    DIRECTION INPUT ;
    USE SIGNAL ;
    ANTENNAGATEAREA 0.666400 ;
    ANTENNADIFFAREA 0.438500 ;
    PORT
      LAYER Metal2 ;
        RECT 1679.720 1098.880 1680.840 1100.000 ;
    END
  END user_wb_dat_i[18]
  PIN user_wb_dat_i[19]
    DIRECTION INPUT ;
    USE SIGNAL ;
    ANTENNAGATEAREA 0.666400 ;
    ANTENNADIFFAREA 0.438500 ;
    PORT
      LAYER Metal2 ;
        RECT 1698.200 1098.880 1699.320 1100.000 ;
    END
  END user_wb_dat_i[19]
  PIN user_wb_dat_i[1]
    DIRECTION INPUT ;
    USE SIGNAL ;
    ANTENNAGATEAREA 0.666400 ;
    ANTENNADIFFAREA 0.438500 ;
    PORT
      LAYER Metal2 ;
        RECT 1365.560 1098.880 1366.680 1100.000 ;
    END
  END user_wb_dat_i[1]
  PIN user_wb_dat_i[20]
    DIRECTION INPUT ;
    USE SIGNAL ;
    ANTENNAGATEAREA 0.666400 ;
    ANTENNADIFFAREA 0.438500 ;
    PORT
      LAYER Metal2 ;
        RECT 1716.680 1098.880 1717.800 1100.000 ;
    END
  END user_wb_dat_i[20]
  PIN user_wb_dat_i[21]
    DIRECTION INPUT ;
    USE SIGNAL ;
    ANTENNAGATEAREA 0.666400 ;
    ANTENNADIFFAREA 0.438500 ;
    PORT
      LAYER Metal2 ;
        RECT 1735.160 1098.880 1736.280 1100.000 ;
    END
  END user_wb_dat_i[21]
  PIN user_wb_dat_i[22]
    DIRECTION INPUT ;
    USE SIGNAL ;
    ANTENNAGATEAREA 0.666400 ;
    ANTENNADIFFAREA 0.438500 ;
    PORT
      LAYER Metal2 ;
        RECT 1753.640 1098.880 1754.760 1100.000 ;
    END
  END user_wb_dat_i[22]
  PIN user_wb_dat_i[23]
    DIRECTION INPUT ;
    USE SIGNAL ;
    ANTENNAGATEAREA 0.666400 ;
    ANTENNADIFFAREA 0.438500 ;
    PORT
      LAYER Metal2 ;
        RECT 1772.120 1098.880 1773.240 1100.000 ;
    END
  END user_wb_dat_i[23]
  PIN user_wb_dat_i[24]
    DIRECTION INPUT ;
    USE SIGNAL ;
    ANTENNAGATEAREA 0.666400 ;
    ANTENNADIFFAREA 0.438500 ;
    PORT
      LAYER Metal2 ;
        RECT 1790.600 1098.880 1791.720 1100.000 ;
    END
  END user_wb_dat_i[24]
  PIN user_wb_dat_i[25]
    DIRECTION INPUT ;
    USE SIGNAL ;
    ANTENNAGATEAREA 0.666400 ;
    ANTENNADIFFAREA 0.438500 ;
    PORT
      LAYER Metal2 ;
        RECT 1809.080 1098.880 1810.200 1100.000 ;
    END
  END user_wb_dat_i[25]
  PIN user_wb_dat_i[26]
    DIRECTION INPUT ;
    USE SIGNAL ;
    ANTENNAGATEAREA 0.666400 ;
    ANTENNADIFFAREA 0.438500 ;
    PORT
      LAYER Metal2 ;
        RECT 1827.560 1098.880 1828.680 1100.000 ;
    END
  END user_wb_dat_i[26]
  PIN user_wb_dat_i[27]
    DIRECTION INPUT ;
    USE SIGNAL ;
    ANTENNAGATEAREA 0.666400 ;
    ANTENNADIFFAREA 0.438500 ;
    PORT
      LAYER Metal2 ;
        RECT 1846.040 1098.880 1847.160 1100.000 ;
    END
  END user_wb_dat_i[27]
  PIN user_wb_dat_i[28]
    DIRECTION INPUT ;
    USE SIGNAL ;
    ANTENNAGATEAREA 0.666400 ;
    ANTENNADIFFAREA 0.438500 ;
    PORT
      LAYER Metal2 ;
        RECT 1864.520 1098.880 1865.640 1100.000 ;
    END
  END user_wb_dat_i[28]
  PIN user_wb_dat_i[29]
    DIRECTION INPUT ;
    USE SIGNAL ;
    ANTENNAGATEAREA 0.666400 ;
    ANTENNADIFFAREA 0.438500 ;
    PORT
      LAYER Metal2 ;
        RECT 1883.000 1098.880 1884.120 1100.000 ;
    END
  END user_wb_dat_i[29]
  PIN user_wb_dat_i[2]
    DIRECTION INPUT ;
    USE SIGNAL ;
    ANTENNAGATEAREA 0.666400 ;
    ANTENNADIFFAREA 0.438500 ;
    PORT
      LAYER Metal2 ;
        RECT 1384.040 1098.880 1385.160 1100.000 ;
    END
  END user_wb_dat_i[2]
  PIN user_wb_dat_i[30]
    DIRECTION INPUT ;
    USE SIGNAL ;
    ANTENNAGATEAREA 0.666400 ;
    ANTENNADIFFAREA 0.438500 ;
    PORT
      LAYER Metal2 ;
        RECT 1901.480 1098.880 1902.600 1100.000 ;
    END
  END user_wb_dat_i[30]
  PIN user_wb_dat_i[31]
    DIRECTION INPUT ;
    USE SIGNAL ;
    ANTENNAGATEAREA 0.666400 ;
    ANTENNADIFFAREA 0.438500 ;
    PORT
      LAYER Metal2 ;
        RECT 1919.960 1098.880 1921.080 1100.000 ;
    END
  END user_wb_dat_i[31]
  PIN user_wb_dat_i[3]
    DIRECTION INPUT ;
    USE SIGNAL ;
    ANTENNAGATEAREA 0.666400 ;
    ANTENNADIFFAREA 0.438500 ;
    PORT
      LAYER Metal2 ;
        RECT 1402.520 1098.880 1403.640 1100.000 ;
    END
  END user_wb_dat_i[3]
  PIN user_wb_dat_i[4]
    DIRECTION INPUT ;
    USE SIGNAL ;
    ANTENNAGATEAREA 0.666400 ;
    ANTENNADIFFAREA 0.438500 ;
    PORT
      LAYER Metal2 ;
        RECT 1421.000 1098.880 1422.120 1100.000 ;
    END
  END user_wb_dat_i[4]
  PIN user_wb_dat_i[5]
    DIRECTION INPUT ;
    USE SIGNAL ;
    ANTENNAGATEAREA 0.666400 ;
    ANTENNADIFFAREA 0.438500 ;
    PORT
      LAYER Metal2 ;
        RECT 1439.480 1098.880 1440.600 1100.000 ;
    END
  END user_wb_dat_i[5]
  PIN user_wb_dat_i[6]
    DIRECTION INPUT ;
    USE SIGNAL ;
    ANTENNAGATEAREA 0.666400 ;
    ANTENNADIFFAREA 0.438500 ;
    PORT
      LAYER Metal2 ;
        RECT 1457.960 1098.880 1459.080 1100.000 ;
    END
  END user_wb_dat_i[6]
  PIN user_wb_dat_i[7]
    DIRECTION INPUT ;
    USE SIGNAL ;
    ANTENNAGATEAREA 0.666400 ;
    ANTENNADIFFAREA 0.438500 ;
    PORT
      LAYER Metal2 ;
        RECT 1476.440 1098.880 1477.560 1100.000 ;
    END
  END user_wb_dat_i[7]
  PIN user_wb_dat_i[8]
    DIRECTION INPUT ;
    USE SIGNAL ;
    ANTENNAGATEAREA 0.666400 ;
    ANTENNADIFFAREA 0.438500 ;
    PORT
      LAYER Metal2 ;
        RECT 1494.920 1098.880 1496.040 1100.000 ;
    END
  END user_wb_dat_i[8]
  PIN user_wb_dat_i[9]
    DIRECTION INPUT ;
    USE SIGNAL ;
    ANTENNAGATEAREA 0.666400 ;
    ANTENNADIFFAREA 0.438500 ;
    PORT
      LAYER Metal2 ;
        RECT 1513.400 1098.880 1514.520 1100.000 ;
    END
  END user_wb_dat_i[9]
  PIN user_wb_dat_o[0]
    DIRECTION OUTPUT ;
    USE SIGNAL ;
    ANTENNADIFFAREA 1.237600 ;
    PORT
      LAYER Metal2 ;
        RECT 755.720 1098.880 756.840 1100.000 ;
    END
  END user_wb_dat_o[0]
  PIN user_wb_dat_o[10]
    DIRECTION OUTPUT ;
    USE SIGNAL ;
    ANTENNADIFFAREA 1.237600 ;
    PORT
      LAYER Metal2 ;
        RECT 940.520 1098.880 941.640 1100.000 ;
    END
  END user_wb_dat_o[10]
  PIN user_wb_dat_o[11]
    DIRECTION OUTPUT ;
    USE SIGNAL ;
    ANTENNADIFFAREA 1.237600 ;
    PORT
      LAYER Metal2 ;
        RECT 959.000 1098.880 960.120 1100.000 ;
    END
  END user_wb_dat_o[11]
  PIN user_wb_dat_o[12]
    DIRECTION OUTPUT ;
    USE SIGNAL ;
    ANTENNADIFFAREA 1.237600 ;
    PORT
      LAYER Metal2 ;
        RECT 977.480 1098.880 978.600 1100.000 ;
    END
  END user_wb_dat_o[12]
  PIN user_wb_dat_o[13]
    DIRECTION OUTPUT ;
    USE SIGNAL ;
    ANTENNADIFFAREA 1.237600 ;
    PORT
      LAYER Metal2 ;
        RECT 995.960 1098.880 997.080 1100.000 ;
    END
  END user_wb_dat_o[13]
  PIN user_wb_dat_o[14]
    DIRECTION OUTPUT ;
    USE SIGNAL ;
    ANTENNADIFFAREA 1.237600 ;
    PORT
      LAYER Metal2 ;
        RECT 1014.440 1098.880 1015.560 1100.000 ;
    END
  END user_wb_dat_o[14]
  PIN user_wb_dat_o[15]
    DIRECTION OUTPUT ;
    USE SIGNAL ;
    ANTENNADIFFAREA 1.237600 ;
    PORT
      LAYER Metal2 ;
        RECT 1032.920 1098.880 1034.040 1100.000 ;
    END
  END user_wb_dat_o[15]
  PIN user_wb_dat_o[16]
    DIRECTION OUTPUT ;
    USE SIGNAL ;
    ANTENNADIFFAREA 1.237600 ;
    PORT
      LAYER Metal2 ;
        RECT 1051.400 1098.880 1052.520 1100.000 ;
    END
  END user_wb_dat_o[16]
  PIN user_wb_dat_o[17]
    DIRECTION OUTPUT ;
    USE SIGNAL ;
    ANTENNADIFFAREA 1.237600 ;
    PORT
      LAYER Metal2 ;
        RECT 1069.880 1098.880 1071.000 1100.000 ;
    END
  END user_wb_dat_o[17]
  PIN user_wb_dat_o[18]
    DIRECTION OUTPUT ;
    USE SIGNAL ;
    ANTENNADIFFAREA 1.237600 ;
    PORT
      LAYER Metal2 ;
        RECT 1088.360 1098.880 1089.480 1100.000 ;
    END
  END user_wb_dat_o[18]
  PIN user_wb_dat_o[19]
    DIRECTION OUTPUT ;
    USE SIGNAL ;
    ANTENNADIFFAREA 1.237600 ;
    PORT
      LAYER Metal2 ;
        RECT 1106.840 1098.880 1107.960 1100.000 ;
    END
  END user_wb_dat_o[19]
  PIN user_wb_dat_o[1]
    DIRECTION OUTPUT ;
    USE SIGNAL ;
    ANTENNADIFFAREA 1.237600 ;
    PORT
      LAYER Metal2 ;
        RECT 774.200 1098.880 775.320 1100.000 ;
    END
  END user_wb_dat_o[1]
  PIN user_wb_dat_o[20]
    DIRECTION OUTPUT ;
    USE SIGNAL ;
    ANTENNADIFFAREA 1.237600 ;
    PORT
      LAYER Metal2 ;
        RECT 1125.320 1098.880 1126.440 1100.000 ;
    END
  END user_wb_dat_o[20]
  PIN user_wb_dat_o[21]
    DIRECTION OUTPUT ;
    USE SIGNAL ;
    ANTENNADIFFAREA 1.237600 ;
    PORT
      LAYER Metal2 ;
        RECT 1143.800 1098.880 1144.920 1100.000 ;
    END
  END user_wb_dat_o[21]
  PIN user_wb_dat_o[22]
    DIRECTION OUTPUT ;
    USE SIGNAL ;
    ANTENNADIFFAREA 1.237600 ;
    PORT
      LAYER Metal2 ;
        RECT 1162.280 1098.880 1163.400 1100.000 ;
    END
  END user_wb_dat_o[22]
  PIN user_wb_dat_o[23]
    DIRECTION OUTPUT ;
    USE SIGNAL ;
    ANTENNADIFFAREA 1.237600 ;
    PORT
      LAYER Metal2 ;
        RECT 1180.760 1098.880 1181.880 1100.000 ;
    END
  END user_wb_dat_o[23]
  PIN user_wb_dat_o[24]
    DIRECTION OUTPUT ;
    USE SIGNAL ;
    ANTENNADIFFAREA 1.237600 ;
    PORT
      LAYER Metal2 ;
        RECT 1199.240 1098.880 1200.360 1100.000 ;
    END
  END user_wb_dat_o[24]
  PIN user_wb_dat_o[25]
    DIRECTION OUTPUT ;
    USE SIGNAL ;
    ANTENNADIFFAREA 1.237600 ;
    PORT
      LAYER Metal2 ;
        RECT 1217.720 1098.880 1218.840 1100.000 ;
    END
  END user_wb_dat_o[25]
  PIN user_wb_dat_o[26]
    DIRECTION OUTPUT ;
    USE SIGNAL ;
    ANTENNADIFFAREA 1.237600 ;
    PORT
      LAYER Metal2 ;
        RECT 1236.200 1098.880 1237.320 1100.000 ;
    END
  END user_wb_dat_o[26]
  PIN user_wb_dat_o[27]
    DIRECTION OUTPUT ;
    USE SIGNAL ;
    ANTENNADIFFAREA 1.237600 ;
    PORT
      LAYER Metal2 ;
        RECT 1254.680 1098.880 1255.800 1100.000 ;
    END
  END user_wb_dat_o[27]
  PIN user_wb_dat_o[28]
    DIRECTION OUTPUT ;
    USE SIGNAL ;
    ANTENNADIFFAREA 1.237600 ;
    PORT
      LAYER Metal2 ;
        RECT 1273.160 1098.880 1274.280 1100.000 ;
    END
  END user_wb_dat_o[28]
  PIN user_wb_dat_o[29]
    DIRECTION OUTPUT ;
    USE SIGNAL ;
    ANTENNADIFFAREA 1.237600 ;
    PORT
      LAYER Metal2 ;
        RECT 1291.640 1098.880 1292.760 1100.000 ;
    END
  END user_wb_dat_o[29]
  PIN user_wb_dat_o[2]
    DIRECTION OUTPUT ;
    USE SIGNAL ;
    ANTENNADIFFAREA 1.237600 ;
    PORT
      LAYER Metal2 ;
        RECT 792.680 1098.880 793.800 1100.000 ;
    END
  END user_wb_dat_o[2]
  PIN user_wb_dat_o[30]
    DIRECTION OUTPUT ;
    USE SIGNAL ;
    ANTENNADIFFAREA 1.237600 ;
    PORT
      LAYER Metal2 ;
        RECT 1310.120 1098.880 1311.240 1100.000 ;
    END
  END user_wb_dat_o[30]
  PIN user_wb_dat_o[31]
    DIRECTION OUTPUT ;
    USE SIGNAL ;
    ANTENNADIFFAREA 1.237600 ;
    PORT
      LAYER Metal2 ;
        RECT 1328.600 1098.880 1329.720 1100.000 ;
    END
  END user_wb_dat_o[31]
  PIN user_wb_dat_o[3]
    DIRECTION OUTPUT ;
    USE SIGNAL ;
    ANTENNADIFFAREA 1.237600 ;
    PORT
      LAYER Metal2 ;
        RECT 811.160 1098.880 812.280 1100.000 ;
    END
  END user_wb_dat_o[3]
  PIN user_wb_dat_o[4]
    DIRECTION OUTPUT ;
    USE SIGNAL ;
    ANTENNADIFFAREA 1.237600 ;
    PORT
      LAYER Metal2 ;
        RECT 829.640 1098.880 830.760 1100.000 ;
    END
  END user_wb_dat_o[4]
  PIN user_wb_dat_o[5]
    DIRECTION OUTPUT ;
    USE SIGNAL ;
    ANTENNADIFFAREA 1.237600 ;
    PORT
      LAYER Metal2 ;
        RECT 848.120 1098.880 849.240 1100.000 ;
    END
  END user_wb_dat_o[5]
  PIN user_wb_dat_o[6]
    DIRECTION OUTPUT ;
    USE SIGNAL ;
    ANTENNADIFFAREA 1.237600 ;
    PORT
      LAYER Metal2 ;
        RECT 866.600 1098.880 867.720 1100.000 ;
    END
  END user_wb_dat_o[6]
  PIN user_wb_dat_o[7]
    DIRECTION OUTPUT ;
    USE SIGNAL ;
    ANTENNADIFFAREA 1.237600 ;
    PORT
      LAYER Metal2 ;
        RECT 885.080 1098.880 886.200 1100.000 ;
    END
  END user_wb_dat_o[7]
  PIN user_wb_dat_o[8]
    DIRECTION OUTPUT ;
    USE SIGNAL ;
    ANTENNADIFFAREA 1.237600 ;
    PORT
      LAYER Metal2 ;
        RECT 903.560 1098.880 904.680 1100.000 ;
    END
  END user_wb_dat_o[8]
  PIN user_wb_dat_o[9]
    DIRECTION OUTPUT ;
    USE SIGNAL ;
    ANTENNADIFFAREA 1.237600 ;
    PORT
      LAYER Metal2 ;
        RECT 922.040 1098.880 923.160 1100.000 ;
    END
  END user_wb_dat_o[9]
  PIN user_wb_rst_o
    DIRECTION OUTPUT ;
    USE SIGNAL ;
    ANTENNADIFFAREA 1.237600 ;
    PORT
      LAYER Metal2 ;
        RECT 1938.440 1098.880 1939.560 1100.000 ;
    END
  END user_wb_rst_o
  PIN user_wb_sel_o[0]
    DIRECTION OUTPUT ;
    USE SIGNAL ;
    ANTENNADIFFAREA 1.237600 ;
    PORT
      LAYER Metal2 ;
        RECT 90.440 1098.880 91.560 1100.000 ;
    END
  END user_wb_sel_o[0]
  PIN user_wb_sel_o[1]
    DIRECTION OUTPUT ;
    USE SIGNAL ;
    ANTENNADIFFAREA 1.237600 ;
    PORT
      LAYER Metal2 ;
        RECT 108.920 1098.880 110.040 1100.000 ;
    END
  END user_wb_sel_o[1]
  PIN user_wb_sel_o[2]
    DIRECTION OUTPUT ;
    USE SIGNAL ;
    ANTENNADIFFAREA 1.237600 ;
    PORT
      LAYER Metal2 ;
        RECT 127.400 1098.880 128.520 1100.000 ;
    END
  END user_wb_sel_o[2]
  PIN user_wb_sel_o[3]
    DIRECTION OUTPUT ;
    USE SIGNAL ;
    ANTENNADIFFAREA 1.237600 ;
    PORT
      LAYER Metal2 ;
        RECT 145.880 1098.880 147.000 1100.000 ;
    END
  END user_wb_sel_o[3]
  PIN user_wb_stb_o
    DIRECTION OUTPUT ;
    USE SIGNAL ;
    ANTENNADIFFAREA 1.237600 ;
    PORT
      LAYER Metal2 ;
        RECT 1975.400 1098.880 1976.520 1100.000 ;
    END
  END user_wb_stb_o
  PIN user_wb_we_o
    DIRECTION OUTPUT ;
    USE SIGNAL ;
    ANTENNADIFFAREA 1.237600 ;
    PORT
      LAYER Metal2 ;
        RECT 1993.880 1098.880 1995.000 1100.000 ;
    END
  END user_wb_we_o
  OBS
      LAYER Nwell ;
        RECT 23.650 30.930 2874.910 1066.670 ;
      LAYER Metal1 ;
        RECT 24.080 31.060 2874.480 1066.540 ;
      LAYER Metal2 ;
        RECT 25.340 1098.580 90.140 1099.700 ;
        RECT 91.860 1098.580 108.620 1099.700 ;
        RECT 110.340 1098.580 127.100 1099.700 ;
        RECT 128.820 1098.580 145.580 1099.700 ;
        RECT 147.300 1098.580 164.060 1099.700 ;
        RECT 165.780 1098.580 182.540 1099.700 ;
        RECT 184.260 1098.580 201.020 1099.700 ;
        RECT 202.740 1098.580 219.500 1099.700 ;
        RECT 221.220 1098.580 237.980 1099.700 ;
        RECT 239.700 1098.580 256.460 1099.700 ;
        RECT 258.180 1098.580 274.940 1099.700 ;
        RECT 276.660 1098.580 293.420 1099.700 ;
        RECT 295.140 1098.580 311.900 1099.700 ;
        RECT 313.620 1098.580 330.380 1099.700 ;
        RECT 332.100 1098.580 348.860 1099.700 ;
        RECT 350.580 1098.580 367.340 1099.700 ;
        RECT 369.060 1098.580 385.820 1099.700 ;
        RECT 387.540 1098.580 404.300 1099.700 ;
        RECT 406.020 1098.580 422.780 1099.700 ;
        RECT 424.500 1098.580 441.260 1099.700 ;
        RECT 442.980 1098.580 459.740 1099.700 ;
        RECT 461.460 1098.580 478.220 1099.700 ;
        RECT 479.940 1098.580 496.700 1099.700 ;
        RECT 498.420 1098.580 515.180 1099.700 ;
        RECT 516.900 1098.580 533.660 1099.700 ;
        RECT 535.380 1098.580 552.140 1099.700 ;
        RECT 553.860 1098.580 570.620 1099.700 ;
        RECT 572.340 1098.580 589.100 1099.700 ;
        RECT 590.820 1098.580 607.580 1099.700 ;
        RECT 609.300 1098.580 626.060 1099.700 ;
        RECT 627.780 1098.580 644.540 1099.700 ;
        RECT 646.260 1098.580 663.020 1099.700 ;
        RECT 664.740 1098.580 681.500 1099.700 ;
        RECT 683.220 1098.580 699.980 1099.700 ;
        RECT 701.700 1098.580 718.460 1099.700 ;
        RECT 720.180 1098.580 736.940 1099.700 ;
        RECT 738.660 1098.580 755.420 1099.700 ;
        RECT 757.140 1098.580 773.900 1099.700 ;
        RECT 775.620 1098.580 792.380 1099.700 ;
        RECT 794.100 1098.580 810.860 1099.700 ;
        RECT 812.580 1098.580 829.340 1099.700 ;
        RECT 831.060 1098.580 847.820 1099.700 ;
        RECT 849.540 1098.580 866.300 1099.700 ;
        RECT 868.020 1098.580 884.780 1099.700 ;
        RECT 886.500 1098.580 903.260 1099.700 ;
        RECT 904.980 1098.580 921.740 1099.700 ;
        RECT 923.460 1098.580 940.220 1099.700 ;
        RECT 941.940 1098.580 958.700 1099.700 ;
        RECT 960.420 1098.580 977.180 1099.700 ;
        RECT 978.900 1098.580 995.660 1099.700 ;
        RECT 997.380 1098.580 1014.140 1099.700 ;
        RECT 1015.860 1098.580 1032.620 1099.700 ;
        RECT 1034.340 1098.580 1051.100 1099.700 ;
        RECT 1052.820 1098.580 1069.580 1099.700 ;
        RECT 1071.300 1098.580 1088.060 1099.700 ;
        RECT 1089.780 1098.580 1106.540 1099.700 ;
        RECT 1108.260 1098.580 1125.020 1099.700 ;
        RECT 1126.740 1098.580 1143.500 1099.700 ;
        RECT 1145.220 1098.580 1161.980 1099.700 ;
        RECT 1163.700 1098.580 1180.460 1099.700 ;
        RECT 1182.180 1098.580 1198.940 1099.700 ;
        RECT 1200.660 1098.580 1217.420 1099.700 ;
        RECT 1219.140 1098.580 1235.900 1099.700 ;
        RECT 1237.620 1098.580 1254.380 1099.700 ;
        RECT 1256.100 1098.580 1272.860 1099.700 ;
        RECT 1274.580 1098.580 1291.340 1099.700 ;
        RECT 1293.060 1098.580 1309.820 1099.700 ;
        RECT 1311.540 1098.580 1328.300 1099.700 ;
        RECT 1330.020 1098.580 1346.780 1099.700 ;
        RECT 1348.500 1098.580 1365.260 1099.700 ;
        RECT 1366.980 1098.580 1383.740 1099.700 ;
        RECT 1385.460 1098.580 1402.220 1099.700 ;
        RECT 1403.940 1098.580 1420.700 1099.700 ;
        RECT 1422.420 1098.580 1439.180 1099.700 ;
        RECT 1440.900 1098.580 1457.660 1099.700 ;
        RECT 1459.380 1098.580 1476.140 1099.700 ;
        RECT 1477.860 1098.580 1494.620 1099.700 ;
        RECT 1496.340 1098.580 1513.100 1099.700 ;
        RECT 1514.820 1098.580 1531.580 1099.700 ;
        RECT 1533.300 1098.580 1550.060 1099.700 ;
        RECT 1551.780 1098.580 1568.540 1099.700 ;
        RECT 1570.260 1098.580 1587.020 1099.700 ;
        RECT 1588.740 1098.580 1605.500 1099.700 ;
        RECT 1607.220 1098.580 1623.980 1099.700 ;
        RECT 1625.700 1098.580 1642.460 1099.700 ;
        RECT 1644.180 1098.580 1660.940 1099.700 ;
        RECT 1662.660 1098.580 1679.420 1099.700 ;
        RECT 1681.140 1098.580 1697.900 1099.700 ;
        RECT 1699.620 1098.580 1716.380 1099.700 ;
        RECT 1718.100 1098.580 1734.860 1099.700 ;
        RECT 1736.580 1098.580 1753.340 1099.700 ;
        RECT 1755.060 1098.580 1771.820 1099.700 ;
        RECT 1773.540 1098.580 1790.300 1099.700 ;
        RECT 1792.020 1098.580 1808.780 1099.700 ;
        RECT 1810.500 1098.580 1827.260 1099.700 ;
        RECT 1828.980 1098.580 1845.740 1099.700 ;
        RECT 1847.460 1098.580 1864.220 1099.700 ;
        RECT 1865.940 1098.580 1882.700 1099.700 ;
        RECT 1884.420 1098.580 1901.180 1099.700 ;
        RECT 1902.900 1098.580 1919.660 1099.700 ;
        RECT 1921.380 1098.580 1938.140 1099.700 ;
        RECT 1939.860 1098.580 1956.620 1099.700 ;
        RECT 1958.340 1098.580 1975.100 1099.700 ;
        RECT 1976.820 1098.580 1993.580 1099.700 ;
        RECT 1995.300 1098.580 2012.060 1099.700 ;
        RECT 2013.780 1098.580 2030.540 1099.700 ;
        RECT 2032.260 1098.580 2049.020 1099.700 ;
        RECT 2050.740 1098.580 2067.500 1099.700 ;
        RECT 2069.220 1098.580 2085.980 1099.700 ;
        RECT 2087.700 1098.580 2104.460 1099.700 ;
        RECT 2106.180 1098.580 2122.940 1099.700 ;
        RECT 2124.660 1098.580 2141.420 1099.700 ;
        RECT 2143.140 1098.580 2159.900 1099.700 ;
        RECT 2161.620 1098.580 2178.380 1099.700 ;
        RECT 2180.100 1098.580 2196.860 1099.700 ;
        RECT 2198.580 1098.580 2215.340 1099.700 ;
        RECT 2217.060 1098.580 2233.820 1099.700 ;
        RECT 2235.540 1098.580 2252.300 1099.700 ;
        RECT 2254.020 1098.580 2270.780 1099.700 ;
        RECT 2272.500 1098.580 2289.260 1099.700 ;
        RECT 2290.980 1098.580 2307.740 1099.700 ;
        RECT 2309.460 1098.580 2326.220 1099.700 ;
        RECT 2327.940 1098.580 2344.700 1099.700 ;
        RECT 2346.420 1098.580 2363.180 1099.700 ;
        RECT 2364.900 1098.580 2381.660 1099.700 ;
        RECT 2383.380 1098.580 2400.140 1099.700 ;
        RECT 2401.860 1098.580 2418.620 1099.700 ;
        RECT 2420.340 1098.580 2437.100 1099.700 ;
        RECT 2438.820 1098.580 2455.580 1099.700 ;
        RECT 2457.300 1098.580 2474.060 1099.700 ;
        RECT 2475.780 1098.580 2492.540 1099.700 ;
        RECT 2494.260 1098.580 2511.020 1099.700 ;
        RECT 2512.740 1098.580 2529.500 1099.700 ;
        RECT 2531.220 1098.580 2547.980 1099.700 ;
        RECT 2549.700 1098.580 2566.460 1099.700 ;
        RECT 2568.180 1098.580 2584.940 1099.700 ;
        RECT 2586.660 1098.580 2603.420 1099.700 ;
        RECT 2605.140 1098.580 2621.900 1099.700 ;
        RECT 2623.620 1098.580 2640.380 1099.700 ;
        RECT 2642.100 1098.580 2658.860 1099.700 ;
        RECT 2660.580 1098.580 2677.340 1099.700 ;
        RECT 2679.060 1098.580 2695.820 1099.700 ;
        RECT 2697.540 1098.580 2714.300 1099.700 ;
        RECT 2716.020 1098.580 2732.780 1099.700 ;
        RECT 2734.500 1098.580 2751.260 1099.700 ;
        RECT 2752.980 1098.580 2769.740 1099.700 ;
        RECT 2771.460 1098.580 2788.220 1099.700 ;
        RECT 2789.940 1098.580 2806.700 1099.700 ;
        RECT 2808.420 1098.580 2873.220 1099.700 ;
        RECT 25.340 1.420 2873.220 1098.580 ;
        RECT 25.340 0.090 36.380 1.420 ;
        RECT 38.100 0.090 63.260 1.420 ;
        RECT 64.980 0.090 90.140 1.420 ;
        RECT 91.860 0.090 117.020 1.420 ;
        RECT 118.740 0.090 143.900 1.420 ;
        RECT 145.620 0.090 170.780 1.420 ;
        RECT 172.500 0.090 197.660 1.420 ;
        RECT 199.380 0.090 224.540 1.420 ;
        RECT 226.260 0.090 251.420 1.420 ;
        RECT 253.140 0.090 278.300 1.420 ;
        RECT 280.020 0.090 305.180 1.420 ;
        RECT 306.900 0.090 332.060 1.420 ;
        RECT 333.780 0.090 358.940 1.420 ;
        RECT 360.660 0.090 385.820 1.420 ;
        RECT 387.540 0.090 412.700 1.420 ;
        RECT 414.420 0.090 439.580 1.420 ;
        RECT 441.300 0.090 466.460 1.420 ;
        RECT 468.180 0.090 493.340 1.420 ;
        RECT 495.060 0.090 520.220 1.420 ;
        RECT 521.940 0.090 547.100 1.420 ;
        RECT 548.820 0.090 573.980 1.420 ;
        RECT 575.700 0.090 600.860 1.420 ;
        RECT 602.580 0.090 627.740 1.420 ;
        RECT 629.460 0.090 654.620 1.420 ;
        RECT 656.340 0.090 681.500 1.420 ;
        RECT 683.220 0.090 708.380 1.420 ;
        RECT 710.100 0.090 735.260 1.420 ;
        RECT 736.980 0.090 762.140 1.420 ;
        RECT 763.860 0.090 789.020 1.420 ;
        RECT 790.740 0.090 815.900 1.420 ;
        RECT 817.620 0.090 842.780 1.420 ;
        RECT 844.500 0.090 869.660 1.420 ;
        RECT 871.380 0.090 896.540 1.420 ;
        RECT 898.260 0.090 923.420 1.420 ;
        RECT 925.140 0.090 950.300 1.420 ;
        RECT 952.020 0.090 977.180 1.420 ;
        RECT 978.900 0.090 1004.060 1.420 ;
        RECT 1005.780 0.090 1030.940 1.420 ;
        RECT 1032.660 0.090 1057.820 1.420 ;
        RECT 1059.540 0.090 1084.700 1.420 ;
        RECT 1086.420 0.090 1111.580 1.420 ;
        RECT 1113.300 0.090 1138.460 1.420 ;
        RECT 1140.180 0.090 1165.340 1.420 ;
        RECT 1167.060 0.090 1192.220 1.420 ;
        RECT 1193.940 0.090 1219.100 1.420 ;
        RECT 1220.820 0.090 1245.980 1.420 ;
        RECT 1247.700 0.090 1272.860 1.420 ;
        RECT 1274.580 0.090 1299.740 1.420 ;
        RECT 1301.460 0.090 1326.620 1.420 ;
        RECT 1328.340 0.090 1353.500 1.420 ;
        RECT 1355.220 0.090 1380.380 1.420 ;
        RECT 1382.100 0.090 1407.260 1.420 ;
        RECT 1408.980 0.090 1434.140 1.420 ;
        RECT 1435.860 0.090 1461.020 1.420 ;
        RECT 1462.740 0.090 1487.900 1.420 ;
        RECT 1489.620 0.090 1514.780 1.420 ;
        RECT 1516.500 0.090 1541.660 1.420 ;
        RECT 1543.380 0.090 1568.540 1.420 ;
        RECT 1570.260 0.090 1595.420 1.420 ;
        RECT 1597.140 0.090 1622.300 1.420 ;
        RECT 1624.020 0.090 1649.180 1.420 ;
        RECT 1650.900 0.090 1676.060 1.420 ;
        RECT 1677.780 0.090 1702.940 1.420 ;
        RECT 1704.660 0.090 1729.820 1.420 ;
        RECT 1731.540 0.090 1756.700 1.420 ;
        RECT 1758.420 0.090 1783.580 1.420 ;
        RECT 1785.300 0.090 1810.460 1.420 ;
        RECT 1812.180 0.090 1837.340 1.420 ;
        RECT 1839.060 0.090 1864.220 1.420 ;
        RECT 1865.940 0.090 1891.100 1.420 ;
        RECT 1892.820 0.090 1917.980 1.420 ;
        RECT 1919.700 0.090 1944.860 1.420 ;
        RECT 1946.580 0.090 1971.740 1.420 ;
        RECT 1973.460 0.090 1998.620 1.420 ;
        RECT 2000.340 0.090 2025.500 1.420 ;
        RECT 2027.220 0.090 2052.380 1.420 ;
        RECT 2054.100 0.090 2079.260 1.420 ;
        RECT 2080.980 0.090 2106.140 1.420 ;
        RECT 2107.860 0.090 2133.020 1.420 ;
        RECT 2134.740 0.090 2159.900 1.420 ;
        RECT 2161.620 0.090 2186.780 1.420 ;
        RECT 2188.500 0.090 2213.660 1.420 ;
        RECT 2215.380 0.090 2240.540 1.420 ;
        RECT 2242.260 0.090 2267.420 1.420 ;
        RECT 2269.140 0.090 2294.300 1.420 ;
        RECT 2296.020 0.090 2321.180 1.420 ;
        RECT 2322.900 0.090 2348.060 1.420 ;
        RECT 2349.780 0.090 2374.940 1.420 ;
        RECT 2376.660 0.090 2401.820 1.420 ;
        RECT 2403.540 0.090 2428.700 1.420 ;
        RECT 2430.420 0.090 2455.580 1.420 ;
        RECT 2457.300 0.090 2482.460 1.420 ;
        RECT 2484.180 0.090 2509.340 1.420 ;
        RECT 2511.060 0.090 2536.220 1.420 ;
        RECT 2537.940 0.090 2563.100 1.420 ;
        RECT 2564.820 0.090 2589.980 1.420 ;
        RECT 2591.700 0.090 2616.860 1.420 ;
        RECT 2618.580 0.090 2643.740 1.420 ;
        RECT 2645.460 0.090 2670.620 1.420 ;
        RECT 2672.340 0.090 2697.500 1.420 ;
        RECT 2699.220 0.090 2724.380 1.420 ;
        RECT 2726.100 0.090 2751.260 1.420 ;
        RECT 2752.980 0.090 2778.140 1.420 ;
        RECT 2779.860 0.090 2805.020 1.420 ;
        RECT 2806.740 0.090 2831.900 1.420 ;
        RECT 2833.620 0.090 2858.780 1.420 ;
        RECT 2860.500 0.090 2873.220 1.420 ;
      LAYER Metal3 ;
        RECT 0.840 1054.500 2899.400 1084.020 ;
        RECT 0.840 1052.780 2898.580 1054.500 ;
        RECT 0.840 987.300 2899.400 1052.780 ;
        RECT 0.840 985.580 2898.580 987.300 ;
        RECT 0.840 920.100 2899.400 985.580 ;
        RECT 0.840 918.380 2898.580 920.100 ;
        RECT 0.840 852.900 2899.400 918.380 ;
        RECT 0.840 851.180 2898.580 852.900 ;
        RECT 0.840 785.700 2899.400 851.180 ;
        RECT 0.840 783.980 2898.580 785.700 ;
        RECT 0.840 718.500 2899.400 783.980 ;
        RECT 0.840 716.780 2898.580 718.500 ;
        RECT 0.840 651.300 2899.400 716.780 ;
        RECT 0.840 649.580 2898.580 651.300 ;
        RECT 0.840 584.100 2899.400 649.580 ;
        RECT 0.840 582.380 2898.580 584.100 ;
        RECT 0.840 550.500 2899.400 582.380 ;
        RECT 1.420 548.780 2899.400 550.500 ;
        RECT 0.840 516.900 2899.400 548.780 ;
        RECT 0.840 515.180 2898.580 516.900 ;
        RECT 0.840 449.700 2899.400 515.180 ;
        RECT 0.840 447.980 2898.580 449.700 ;
        RECT 0.840 382.500 2899.400 447.980 ;
        RECT 0.840 380.780 2898.580 382.500 ;
        RECT 0.840 315.300 2899.400 380.780 ;
        RECT 0.840 313.580 2898.580 315.300 ;
        RECT 0.840 248.100 2899.400 313.580 ;
        RECT 0.840 246.380 2898.580 248.100 ;
        RECT 0.840 180.900 2899.400 246.380 ;
        RECT 0.840 179.180 2898.580 180.900 ;
        RECT 0.840 113.700 2899.400 179.180 ;
        RECT 0.840 111.980 2898.580 113.700 ;
        RECT 0.840 46.500 2899.400 111.980 ;
        RECT 0.840 44.780 2898.580 46.500 ;
        RECT 0.840 0.140 2899.400 44.780 ;
      LAYER Metal4 ;
        RECT 50.630 609.070 106.030 1071.190 ;
        RECT 50.000 79.030 106.030 609.070 ;
        RECT 50.630 4.060 106.030 79.030 ;
        RECT 109.130 4.060 127.530 1071.190 ;
        RECT 130.630 4.060 186.030 1071.190 ;
        RECT 189.130 4.060 207.530 1071.190 ;
        RECT 210.630 4.060 266.030 1071.190 ;
        RECT 269.130 4.060 287.530 1071.190 ;
        RECT 290.630 609.070 346.030 1071.190 ;
        RECT 349.130 609.070 367.530 1071.190 ;
        RECT 290.630 79.030 367.530 609.070 ;
        RECT 290.630 4.060 346.030 79.030 ;
        RECT 349.130 4.060 367.530 79.030 ;
        RECT 370.630 4.060 426.030 1071.190 ;
        RECT 429.130 4.060 447.530 1071.190 ;
        RECT 450.630 4.060 506.030 1071.190 ;
        RECT 509.130 4.060 527.530 1071.190 ;
        RECT 530.630 4.060 586.030 1071.190 ;
        RECT 589.130 4.060 607.530 1071.190 ;
        RECT 610.630 4.060 666.030 1071.190 ;
        RECT 669.130 4.060 687.530 1071.190 ;
        RECT 690.630 4.060 746.030 1071.190 ;
        RECT 749.130 4.060 767.530 1071.190 ;
        RECT 770.630 4.060 826.030 1071.190 ;
        RECT 829.130 4.060 847.530 1071.190 ;
        RECT 850.630 4.060 906.030 1071.190 ;
        RECT 909.130 4.060 927.530 1071.190 ;
        RECT 930.630 4.060 986.030 1071.190 ;
        RECT 989.130 4.060 1007.530 1071.190 ;
        RECT 1010.630 4.060 1066.030 1071.190 ;
        RECT 1069.130 4.060 1087.530 1071.190 ;
        RECT 1090.630 4.060 1146.030 1071.190 ;
        RECT 1149.130 4.060 1167.530 1071.190 ;
        RECT 1170.630 4.060 1226.030 1071.190 ;
        RECT 1229.130 4.060 1247.530 1071.190 ;
        RECT 1250.630 4.060 1306.030 1071.190 ;
        RECT 1309.130 4.060 1327.530 1071.190 ;
        RECT 1330.630 4.060 1386.030 1071.190 ;
        RECT 1389.130 4.060 1407.530 1071.190 ;
        RECT 1410.630 4.060 1466.030 1071.190 ;
        RECT 1469.130 4.060 1487.530 1071.190 ;
        RECT 1490.630 4.060 1546.030 1071.190 ;
        RECT 1549.130 4.060 1567.530 1071.190 ;
        RECT 1570.630 4.060 1626.030 1071.190 ;
        RECT 1629.130 4.060 1647.530 1071.190 ;
        RECT 1650.630 4.060 1706.030 1071.190 ;
        RECT 1709.130 4.060 1727.530 1071.190 ;
        RECT 1730.630 4.060 1786.030 1071.190 ;
        RECT 1789.130 4.060 1807.530 1071.190 ;
        RECT 1810.630 4.060 1866.030 1071.190 ;
        RECT 1869.130 4.060 1887.530 1071.190 ;
        RECT 1890.630 4.060 1946.030 1071.190 ;
        RECT 1949.130 4.060 1967.530 1071.190 ;
        RECT 1970.630 4.060 2026.030 1071.190 ;
        RECT 2029.130 4.060 2047.530 1071.190 ;
        RECT 2050.630 4.060 2106.030 1071.190 ;
        RECT 2109.130 4.060 2127.530 1071.190 ;
        RECT 2130.630 4.060 2186.030 1071.190 ;
        RECT 2189.130 609.070 2207.530 1071.190 ;
        RECT 2210.630 609.070 2266.030 1071.190 ;
        RECT 2189.130 79.030 2266.030 609.070 ;
        RECT 2189.130 4.060 2207.530 79.030 ;
        RECT 2210.630 4.060 2266.030 79.030 ;
        RECT 2269.130 4.060 2287.530 1071.190 ;
        RECT 2290.630 4.060 2346.030 1071.190 ;
        RECT 2349.130 4.060 2367.530 1071.190 ;
        RECT 2370.630 4.060 2426.030 1071.190 ;
        RECT 2429.130 4.060 2447.530 1071.190 ;
        RECT 2450.630 791.330 2506.030 1071.190 ;
        RECT 2509.130 791.330 2527.530 1071.190 ;
        RECT 2530.630 791.330 2586.030 1071.190 ;
        RECT 2450.630 698.270 2586.030 791.330 ;
        RECT 2450.630 4.060 2506.030 698.270 ;
        RECT 2509.130 4.060 2527.530 698.270 ;
        RECT 2530.630 4.060 2586.030 698.270 ;
        RECT 2589.130 753.240 2607.530 1071.190 ;
        RECT 2589.130 689.320 2602.795 753.240 ;
        RECT 2606.325 689.320 2607.530 753.240 ;
        RECT 2589.130 4.060 2607.530 689.320 ;
        RECT 2610.630 4.060 2620.530 1071.190 ;
        RECT 2623.630 4.060 2632.030 1071.190 ;
        RECT 2635.130 749.425 2666.030 1071.190 ;
        RECT 2669.130 749.425 2687.530 1071.190 ;
        RECT 2690.630 749.425 2746.030 1071.190 ;
        RECT 2635.130 692.030 2746.030 749.425 ;
        RECT 2635.130 4.060 2666.030 692.030 ;
        RECT 2669.130 4.060 2687.530 692.030 ;
        RECT 2690.630 4.060 2746.030 692.030 ;
        RECT 2749.130 4.060 2767.530 1071.190 ;
        RECT 2770.630 4.060 2826.030 1071.190 ;
        RECT 2829.130 4.060 2847.530 1071.190 ;
        RECT 2850.630 608.200 2870.420 1071.190 ;
        RECT 2850.630 73.880 2851.370 608.200 ;
        RECT 2854.470 73.880 2870.420 608.200 ;
        RECT 2850.630 4.060 2870.420 73.880 ;
        RECT 50.000 0.090 2870.420 4.060 ;
      LAYER Metal5 ;
        RECT 93.580 1053.360 2870.500 1066.270 ;
        RECT 93.580 1023.860 2870.500 1049.660 ;
        RECT 93.580 993.360 2870.500 1020.160 ;
        RECT 93.580 963.860 2870.500 989.660 ;
        RECT 93.580 933.360 2870.500 960.160 ;
        RECT 93.580 903.860 2870.500 929.660 ;
        RECT 93.580 873.360 2870.500 900.160 ;
        RECT 93.580 843.860 2870.500 869.660 ;
        RECT 93.580 813.360 2870.500 840.160 ;
        RECT 93.580 783.860 2870.500 809.660 ;
        RECT 93.580 753.360 2870.500 780.160 ;
        RECT 2636.495 749.660 2706.855 753.360 ;
        RECT 93.580 723.860 2870.500 749.660 ;
        RECT 2504.780 720.160 2570.260 723.860 ;
        RECT 2636.495 720.160 2706.855 723.860 ;
        RECT 93.580 693.360 2870.500 720.160 ;
        RECT 2636.995 689.660 2706.855 693.360 ;
        RECT 93.580 663.860 2870.500 689.660 ;
        RECT 93.580 633.360 2870.500 660.160 ;
        RECT 93.580 603.860 2870.500 629.660 ;
        RECT 93.580 573.360 2870.500 600.160 ;
        RECT 93.580 543.860 2870.500 569.660 ;
        RECT 93.580 513.360 2870.500 540.160 ;
        RECT 93.580 483.860 2870.500 509.660 ;
        RECT 93.580 453.360 2870.500 480.160 ;
        RECT 93.580 423.860 2870.500 449.660 ;
        RECT 93.580 393.360 2870.500 420.160 ;
        RECT 93.580 363.860 2870.500 389.660 ;
        RECT 93.580 333.360 2870.500 360.160 ;
        RECT 93.580 303.860 2870.500 329.660 ;
        RECT 93.580 273.360 2870.500 300.160 ;
        RECT 93.580 243.860 2870.500 269.660 ;
        RECT 93.580 213.360 2870.500 240.160 ;
        RECT 93.580 183.860 2870.500 209.660 ;
        RECT 93.580 153.360 2870.500 180.160 ;
        RECT 93.580 123.860 2870.500 149.660 ;
        RECT 93.580 93.360 2870.500 120.160 ;
        RECT 93.580 63.860 2870.500 89.660 ;
        RECT 93.580 31.730 2870.500 60.160 ;
  END
END caravel_core
END LIBRARY

